VERSION 5.7 ;
BUSBITCHARS "[]" ;
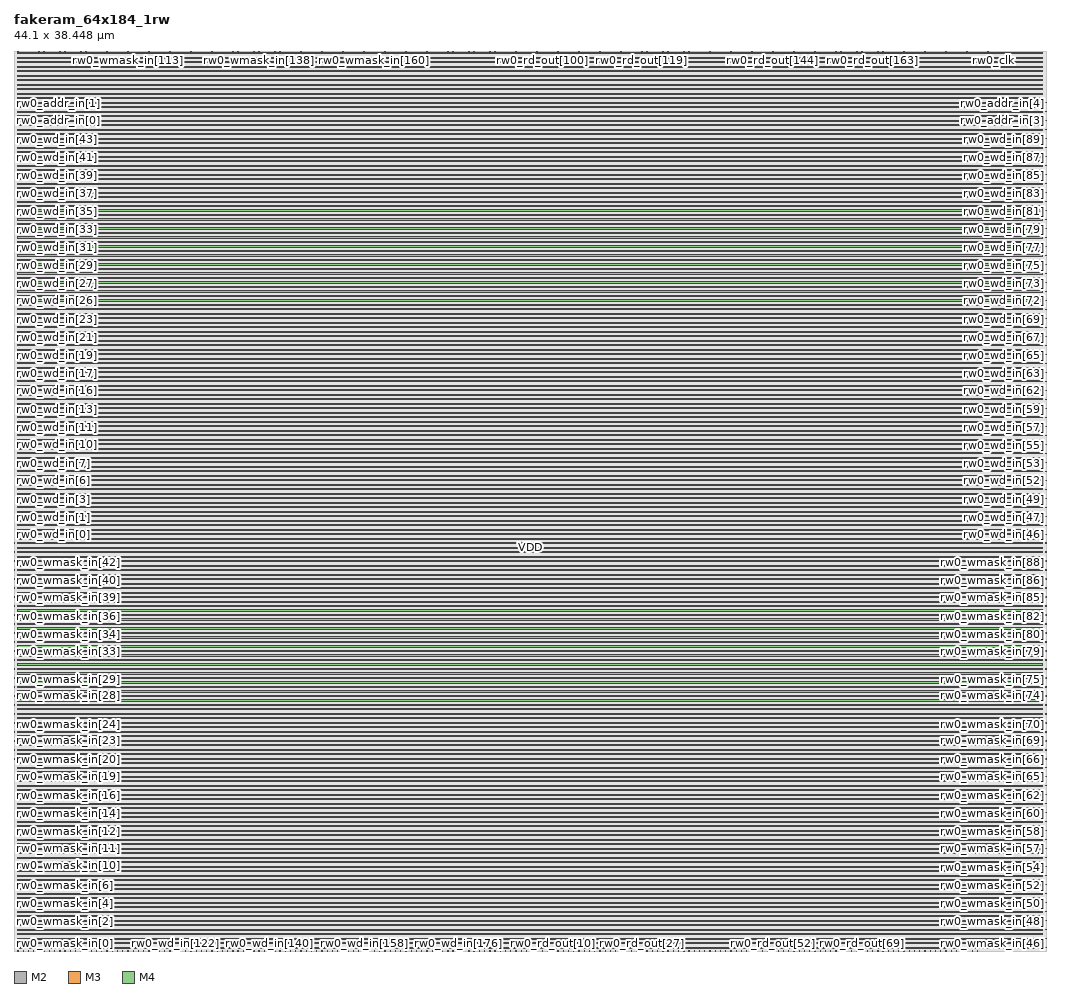
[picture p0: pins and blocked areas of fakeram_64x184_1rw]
MACRO fakeram_64x184_1rw
  FOREIGN fakeram_64x184_1rw 0 0 ;
  SYMMETRY X Y R90 ;
  SIZE 44.100 BY 38.448 ;
  CLASS BLOCK ;
  PIN rw0_wmask_in[0]
    DIRECTION INPUT ;
    USE SIGNAL ;
    SHAPE ABUTMENT ;
    PORT
      LAYER M2 ;
      RECT 0.000 0.138 0.036 0.150 ;
    END
  END rw0_wmask_in[0]
  PIN rw0_wmask_in[1]
    DIRECTION INPUT ;
    USE SIGNAL ;
    SHAPE ABUTMENT ;
    PORT
      LAYER M2 ;
      RECT 0.000 0.522 0.036 0.534 ;
    END
  END rw0_wmask_in[1]
  PIN rw0_wmask_in[2]
    DIRECTION INPUT ;
    USE SIGNAL ;
    SHAPE ABUTMENT ;
    PORT
      LAYER M2 ;
      RECT 0.000 0.906 0.036 0.918 ;
    END
  END rw0_wmask_in[2]
  PIN rw0_wmask_in[3]
    DIRECTION INPUT ;
    USE SIGNAL ;
    SHAPE ABUTMENT ;
    PORT
      LAYER M2 ;
      RECT 0.000 1.290 0.036 1.302 ;
    END
  END rw0_wmask_in[3]
  PIN rw0_wmask_in[4]
    DIRECTION INPUT ;
    USE SIGNAL ;
    SHAPE ABUTMENT ;
    PORT
      LAYER M2 ;
      RECT 0.000 1.674 0.036 1.686 ;
    END
  END rw0_wmask_in[4]
  PIN rw0_wmask_in[5]
    DIRECTION INPUT ;
    USE SIGNAL ;
    SHAPE ABUTMENT ;
    PORT
      LAYER M2 ;
      RECT 0.000 2.058 0.036 2.070 ;
    END
  END rw0_wmask_in[5]
  PIN rw0_wmask_in[6]
    DIRECTION INPUT ;
    USE SIGNAL ;
    SHAPE ABUTMENT ;
    PORT
      LAYER M2 ;
      RECT 0.000 2.442 0.036 2.454 ;
    END
  END rw0_wmask_in[6]
  PIN rw0_wmask_in[7]
    DIRECTION INPUT ;
    USE SIGNAL ;
    SHAPE ABUTMENT ;
    PORT
      LAYER M2 ;
      RECT 0.000 2.826 0.036 2.838 ;
    END
  END rw0_wmask_in[7]
  PIN rw0_wmask_in[8]
    DIRECTION INPUT ;
    USE SIGNAL ;
    SHAPE ABUTMENT ;
    PORT
      LAYER M2 ;
      RECT 0.000 3.210 0.036 3.222 ;
    END
  END rw0_wmask_in[8]
  PIN rw0_wmask_in[9]
    DIRECTION INPUT ;
    USE SIGNAL ;
    SHAPE ABUTMENT ;
    PORT
      LAYER M2 ;
      RECT 0.000 3.594 0.036 3.606 ;
    END
  END rw0_wmask_in[9]
  PIN rw0_wmask_in[10]
    DIRECTION INPUT ;
    USE SIGNAL ;
    SHAPE ABUTMENT ;
    PORT
      LAYER M2 ;
      RECT 0.000 3.978 0.036 3.990 ;
    END
  END rw0_wmask_in[10]
  PIN rw0_wmask_in[11]
    DIRECTION INPUT ;
    USE SIGNAL ;
    SHAPE ABUTMENT ;
    PORT
      LAYER M2 ;
      RECT 0.000 4.362 0.036 4.374 ;
    END
  END rw0_wmask_in[11]
  PIN rw0_wmask_in[12]
    DIRECTION INPUT ;
    USE SIGNAL ;
    SHAPE ABUTMENT ;
    PORT
      LAYER M2 ;
      RECT 0.000 4.746 0.036 4.758 ;
    END
  END rw0_wmask_in[12]
  PIN rw0_wmask_in[13]
    DIRECTION INPUT ;
    USE SIGNAL ;
    SHAPE ABUTMENT ;
    PORT
      LAYER M2 ;
      RECT 0.000 5.130 0.036 5.142 ;
    END
  END rw0_wmask_in[13]
  PIN rw0_wmask_in[14]
    DIRECTION INPUT ;
    USE SIGNAL ;
    SHAPE ABUTMENT ;
    PORT
      LAYER M2 ;
      RECT 0.000 5.514 0.036 5.526 ;
    END
  END rw0_wmask_in[14]
  PIN rw0_wmask_in[15]
    DIRECTION INPUT ;
    USE SIGNAL ;
    SHAPE ABUTMENT ;
    PORT
      LAYER M2 ;
      RECT 0.000 5.898 0.036 5.910 ;
    END
  END rw0_wmask_in[15]
  PIN rw0_wmask_in[16]
    DIRECTION INPUT ;
    USE SIGNAL ;
    SHAPE ABUTMENT ;
    PORT
      LAYER M2 ;
      RECT 0.000 6.282 0.036 6.294 ;
    END
  END rw0_wmask_in[16]
  PIN rw0_wmask_in[17]
    DIRECTION INPUT ;
    USE SIGNAL ;
    SHAPE ABUTMENT ;
    PORT
      LAYER M2 ;
      RECT 0.000 6.666 0.036 6.678 ;
    END
  END rw0_wmask_in[17]
  PIN rw0_wmask_in[18]
    DIRECTION INPUT ;
    USE SIGNAL ;
    SHAPE ABUTMENT ;
    PORT
      LAYER M2 ;
      RECT 0.000 7.050 0.036 7.062 ;
    END
  END rw0_wmask_in[18]
  PIN rw0_wmask_in[19]
    DIRECTION INPUT ;
    USE SIGNAL ;
    SHAPE ABUTMENT ;
    PORT
      LAYER M2 ;
      RECT 0.000 7.434 0.036 7.446 ;
    END
  END rw0_wmask_in[19]
  PIN rw0_wmask_in[20]
    DIRECTION INPUT ;
    USE SIGNAL ;
    SHAPE ABUTMENT ;
    PORT
      LAYER M2 ;
      RECT 0.000 7.818 0.036 7.830 ;
    END
  END rw0_wmask_in[20]
  PIN rw0_wmask_in[21]
    DIRECTION INPUT ;
    USE SIGNAL ;
    SHAPE ABUTMENT ;
    PORT
      LAYER M2 ;
      RECT 0.000 8.202 0.036 8.214 ;
    END
  END rw0_wmask_in[21]
  PIN rw0_wmask_in[22]
    DIRECTION INPUT ;
    USE SIGNAL ;
    SHAPE ABUTMENT ;
    PORT
      LAYER M2 ;
      RECT 0.000 8.586 0.036 8.598 ;
    END
  END rw0_wmask_in[22]
  PIN rw0_wmask_in[23]
    DIRECTION INPUT ;
    USE SIGNAL ;
    SHAPE ABUTMENT ;
    PORT
      LAYER M2 ;
      RECT 0.000 8.970 0.036 8.982 ;
    END
  END rw0_wmask_in[23]
  PIN rw0_wmask_in[24]
    DIRECTION INPUT ;
    USE SIGNAL ;
    SHAPE ABUTMENT ;
    PORT
      LAYER M2 ;
      RECT 0.000 9.354 0.036 9.366 ;
    END
  END rw0_wmask_in[24]
  PIN rw0_wmask_in[25]
    DIRECTION INPUT ;
    USE SIGNAL ;
    SHAPE ABUTMENT ;
    PORT
      LAYER M2 ;
      RECT 0.000 9.738 0.036 9.750 ;
    END
  END rw0_wmask_in[25]
  PIN rw0_wmask_in[26]
    DIRECTION INPUT ;
    USE SIGNAL ;
    SHAPE ABUTMENT ;
    PORT
      LAYER M2 ;
      RECT 0.000 10.122 0.036 10.134 ;
    END
  END rw0_wmask_in[26]
  PIN rw0_wmask_in[27]
    DIRECTION INPUT ;
    USE SIGNAL ;
    SHAPE ABUTMENT ;
    PORT
      LAYER M2 ;
      RECT 0.000 10.506 0.036 10.518 ;
    END
  END rw0_wmask_in[27]
  PIN rw0_wmask_in[28]
    DIRECTION INPUT ;
    USE SIGNAL ;
    SHAPE ABUTMENT ;
    PORT
      LAYER M2 ;
      RECT 0.000 10.890 0.036 10.902 ;
    END
  END rw0_wmask_in[28]
  PIN rw0_wmask_in[29]
    DIRECTION INPUT ;
    USE SIGNAL ;
    SHAPE ABUTMENT ;
    PORT
      LAYER M2 ;
      RECT 0.000 11.274 0.036 11.286 ;
    END
  END rw0_wmask_in[29]
  PIN rw0_wmask_in[30]
    DIRECTION INPUT ;
    USE SIGNAL ;
    SHAPE ABUTMENT ;
    PORT
      LAYER M2 ;
      RECT 0.000 11.658 0.036 11.670 ;
    END
  END rw0_wmask_in[30]
  PIN rw0_wmask_in[31]
    DIRECTION INPUT ;
    USE SIGNAL ;
    SHAPE ABUTMENT ;
    PORT
      LAYER M2 ;
      RECT 0.000 12.042 0.036 12.054 ;
    END
  END rw0_wmask_in[31]
  PIN rw0_wmask_in[32]
    DIRECTION INPUT ;
    USE SIGNAL ;
    SHAPE ABUTMENT ;
    PORT
      LAYER M2 ;
      RECT 0.000 12.426 0.036 12.438 ;
    END
  END rw0_wmask_in[32]
  PIN rw0_wmask_in[33]
    DIRECTION INPUT ;
    USE SIGNAL ;
    SHAPE ABUTMENT ;
    PORT
      LAYER M2 ;
      RECT 0.000 12.810 0.036 12.822 ;
    END
  END rw0_wmask_in[33]
  PIN rw0_wmask_in[34]
    DIRECTION INPUT ;
    USE SIGNAL ;
    SHAPE ABUTMENT ;
    PORT
      LAYER M2 ;
      RECT 0.000 13.194 0.036 13.206 ;
    END
  END rw0_wmask_in[34]
  PIN rw0_wmask_in[35]
    DIRECTION INPUT ;
    USE SIGNAL ;
    SHAPE ABUTMENT ;
    PORT
      LAYER M2 ;
      RECT 0.000 13.578 0.036 13.590 ;
    END
  END rw0_wmask_in[35]
  PIN rw0_wmask_in[36]
    DIRECTION INPUT ;
    USE SIGNAL ;
    SHAPE ABUTMENT ;
    PORT
      LAYER M2 ;
      RECT 0.000 13.962 0.036 13.974 ;
    END
  END rw0_wmask_in[36]
  PIN rw0_wmask_in[37]
    DIRECTION INPUT ;
    USE SIGNAL ;
    SHAPE ABUTMENT ;
    PORT
      LAYER M2 ;
      RECT 0.000 14.346 0.036 14.358 ;
    END
  END rw0_wmask_in[37]
  PIN rw0_wmask_in[38]
    DIRECTION INPUT ;
    USE SIGNAL ;
    SHAPE ABUTMENT ;
    PORT
      LAYER M2 ;
      RECT 0.000 14.730 0.036 14.742 ;
    END
  END rw0_wmask_in[38]
  PIN rw0_wmask_in[39]
    DIRECTION INPUT ;
    USE SIGNAL ;
    SHAPE ABUTMENT ;
    PORT
      LAYER M2 ;
      RECT 0.000 15.114 0.036 15.126 ;
    END
  END rw0_wmask_in[39]
  PIN rw0_wmask_in[40]
    DIRECTION INPUT ;
    USE SIGNAL ;
    SHAPE ABUTMENT ;
    PORT
      LAYER M2 ;
      RECT 0.000 15.498 0.036 15.510 ;
    END
  END rw0_wmask_in[40]
  PIN rw0_wmask_in[41]
    DIRECTION INPUT ;
    USE SIGNAL ;
    SHAPE ABUTMENT ;
    PORT
      LAYER M2 ;
      RECT 0.000 15.882 0.036 15.894 ;
    END
  END rw0_wmask_in[41]
  PIN rw0_wmask_in[42]
    DIRECTION INPUT ;
    USE SIGNAL ;
    SHAPE ABUTMENT ;
    PORT
      LAYER M2 ;
      RECT 0.000 16.266 0.036 16.278 ;
    END
  END rw0_wmask_in[42]
  PIN rw0_wmask_in[43]
    DIRECTION INPUT ;
    USE SIGNAL ;
    SHAPE ABUTMENT ;
    PORT
      LAYER M2 ;
      RECT 0.000 16.650 0.036 16.662 ;
    END
  END rw0_wmask_in[43]
  PIN rw0_wmask_in[44]
    DIRECTION INPUT ;
    USE SIGNAL ;
    SHAPE ABUTMENT ;
    PORT
      LAYER M2 ;
      RECT 0.000 17.034 0.036 17.046 ;
    END
  END rw0_wmask_in[44]
  PIN rw0_wmask_in[45]
    DIRECTION INPUT ;
    USE SIGNAL ;
    SHAPE ABUTMENT ;
    PORT
      LAYER M2 ;
      RECT 0.000 17.418 0.036 17.430 ;
    END
  END rw0_wmask_in[45]
  PIN rw0_wmask_in[46]
    DIRECTION INPUT ;
    USE SIGNAL ;
    SHAPE ABUTMENT ;
    PORT
      LAYER M2 ;
      RECT 44.064 0.138 44.100 0.150 ;
    END
  END rw0_wmask_in[46]
  PIN rw0_wmask_in[47]
    DIRECTION INPUT ;
    USE SIGNAL ;
    SHAPE ABUTMENT ;
    PORT
      LAYER M2 ;
      RECT 44.064 0.522 44.100 0.534 ;
    END
  END rw0_wmask_in[47]
  PIN rw0_wmask_in[48]
    DIRECTION INPUT ;
    USE SIGNAL ;
    SHAPE ABUTMENT ;
    PORT
      LAYER M2 ;
      RECT 44.064 0.906 44.100 0.918 ;
    END
  END rw0_wmask_in[48]
  PIN rw0_wmask_in[49]
    DIRECTION INPUT ;
    USE SIGNAL ;
    SHAPE ABUTMENT ;
    PORT
      LAYER M2 ;
      RECT 44.064 1.290 44.100 1.302 ;
    END
  END rw0_wmask_in[49]
  PIN rw0_wmask_in[50]
    DIRECTION INPUT ;
    USE SIGNAL ;
    SHAPE ABUTMENT ;
    PORT
      LAYER M2 ;
      RECT 44.064 1.674 44.100 1.686 ;
    END
  END rw0_wmask_in[50]
  PIN rw0_wmask_in[51]
    DIRECTION INPUT ;
    USE SIGNAL ;
    SHAPE ABUTMENT ;
    PORT
      LAYER M2 ;
      RECT 44.064 2.058 44.100 2.070 ;
    END
  END rw0_wmask_in[51]
  PIN rw0_wmask_in[52]
    DIRECTION INPUT ;
    USE SIGNAL ;
    SHAPE ABUTMENT ;
    PORT
      LAYER M2 ;
      RECT 44.064 2.442 44.100 2.454 ;
    END
  END rw0_wmask_in[52]
  PIN rw0_wmask_in[53]
    DIRECTION INPUT ;
    USE SIGNAL ;
    SHAPE ABUTMENT ;
    PORT
      LAYER M2 ;
      RECT 44.064 2.826 44.100 2.838 ;
    END
  END rw0_wmask_in[53]
  PIN rw0_wmask_in[54]
    DIRECTION INPUT ;
    USE SIGNAL ;
    SHAPE ABUTMENT ;
    PORT
      LAYER M2 ;
      RECT 44.064 3.210 44.100 3.222 ;
    END
  END rw0_wmask_in[54]
  PIN rw0_wmask_in[55]
    DIRECTION INPUT ;
    USE SIGNAL ;
    SHAPE ABUTMENT ;
    PORT
      LAYER M2 ;
      RECT 44.064 3.594 44.100 3.606 ;
    END
  END rw0_wmask_in[55]
  PIN rw0_wmask_in[56]
    DIRECTION INPUT ;
    USE SIGNAL ;
    SHAPE ABUTMENT ;
    PORT
      LAYER M2 ;
      RECT 44.064 3.978 44.100 3.990 ;
    END
  END rw0_wmask_in[56]
  PIN rw0_wmask_in[57]
    DIRECTION INPUT ;
    USE SIGNAL ;
    SHAPE ABUTMENT ;
    PORT
      LAYER M2 ;
      RECT 44.064 4.362 44.100 4.374 ;
    END
  END rw0_wmask_in[57]
  PIN rw0_wmask_in[58]
    DIRECTION INPUT ;
    USE SIGNAL ;
    SHAPE ABUTMENT ;
    PORT
      LAYER M2 ;
      RECT 44.064 4.746 44.100 4.758 ;
    END
  END rw0_wmask_in[58]
  PIN rw0_wmask_in[59]
    DIRECTION INPUT ;
    USE SIGNAL ;
    SHAPE ABUTMENT ;
    PORT
      LAYER M2 ;
      RECT 44.064 5.130 44.100 5.142 ;
    END
  END rw0_wmask_in[59]
  PIN rw0_wmask_in[60]
    DIRECTION INPUT ;
    USE SIGNAL ;
    SHAPE ABUTMENT ;
    PORT
      LAYER M2 ;
      RECT 44.064 5.514 44.100 5.526 ;
    END
  END rw0_wmask_in[60]
  PIN rw0_wmask_in[61]
    DIRECTION INPUT ;
    USE SIGNAL ;
    SHAPE ABUTMENT ;
    PORT
      LAYER M2 ;
      RECT 44.064 5.898 44.100 5.910 ;
    END
  END rw0_wmask_in[61]
  PIN rw0_wmask_in[62]
    DIRECTION INPUT ;
    USE SIGNAL ;
    SHAPE ABUTMENT ;
    PORT
      LAYER M2 ;
      RECT 44.064 6.282 44.100 6.294 ;
    END
  END rw0_wmask_in[62]
  PIN rw0_wmask_in[63]
    DIRECTION INPUT ;
    USE SIGNAL ;
    SHAPE ABUTMENT ;
    PORT
      LAYER M2 ;
      RECT 44.064 6.666 44.100 6.678 ;
    END
  END rw0_wmask_in[63]
  PIN rw0_wmask_in[64]
    DIRECTION INPUT ;
    USE SIGNAL ;
    SHAPE ABUTMENT ;
    PORT
      LAYER M2 ;
      RECT 44.064 7.050 44.100 7.062 ;
    END
  END rw0_wmask_in[64]
  PIN rw0_wmask_in[65]
    DIRECTION INPUT ;
    USE SIGNAL ;
    SHAPE ABUTMENT ;
    PORT
      LAYER M2 ;
      RECT 44.064 7.434 44.100 7.446 ;
    END
  END rw0_wmask_in[65]
  PIN rw0_wmask_in[66]
    DIRECTION INPUT ;
    USE SIGNAL ;
    SHAPE ABUTMENT ;
    PORT
      LAYER M2 ;
      RECT 44.064 7.818 44.100 7.830 ;
    END
  END rw0_wmask_in[66]
  PIN rw0_wmask_in[67]
    DIRECTION INPUT ;
    USE SIGNAL ;
    SHAPE ABUTMENT ;
    PORT
      LAYER M2 ;
      RECT 44.064 8.202 44.100 8.214 ;
    END
  END rw0_wmask_in[67]
  PIN rw0_wmask_in[68]
    DIRECTION INPUT ;
    USE SIGNAL ;
    SHAPE ABUTMENT ;
    PORT
      LAYER M2 ;
      RECT 44.064 8.586 44.100 8.598 ;
    END
  END rw0_wmask_in[68]
  PIN rw0_wmask_in[69]
    DIRECTION INPUT ;
    USE SIGNAL ;
    SHAPE ABUTMENT ;
    PORT
      LAYER M2 ;
      RECT 44.064 8.970 44.100 8.982 ;
    END
  END rw0_wmask_in[69]
  PIN rw0_wmask_in[70]
    DIRECTION INPUT ;
    USE SIGNAL ;
    SHAPE ABUTMENT ;
    PORT
      LAYER M2 ;
      RECT 44.064 9.354 44.100 9.366 ;
    END
  END rw0_wmask_in[70]
  PIN rw0_wmask_in[71]
    DIRECTION INPUT ;
    USE SIGNAL ;
    SHAPE ABUTMENT ;
    PORT
      LAYER M2 ;
      RECT 44.064 9.738 44.100 9.750 ;
    END
  END rw0_wmask_in[71]
  PIN rw0_wmask_in[72]
    DIRECTION INPUT ;
    USE SIGNAL ;
    SHAPE ABUTMENT ;
    PORT
      LAYER M2 ;
      RECT 44.064 10.122 44.100 10.134 ;
    END
  END rw0_wmask_in[72]
  PIN rw0_wmask_in[73]
    DIRECTION INPUT ;
    USE SIGNAL ;
    SHAPE ABUTMENT ;
    PORT
      LAYER M2 ;
      RECT 44.064 10.506 44.100 10.518 ;
    END
  END rw0_wmask_in[73]
  PIN rw0_wmask_in[74]
    DIRECTION INPUT ;
    USE SIGNAL ;
    SHAPE ABUTMENT ;
    PORT
      LAYER M2 ;
      RECT 44.064 10.890 44.100 10.902 ;
    END
  END rw0_wmask_in[74]
  PIN rw0_wmask_in[75]
    DIRECTION INPUT ;
    USE SIGNAL ;
    SHAPE ABUTMENT ;
    PORT
      LAYER M2 ;
      RECT 44.064 11.274 44.100 11.286 ;
    END
  END rw0_wmask_in[75]
  PIN rw0_wmask_in[76]
    DIRECTION INPUT ;
    USE SIGNAL ;
    SHAPE ABUTMENT ;
    PORT
      LAYER M2 ;
      RECT 44.064 11.658 44.100 11.670 ;
    END
  END rw0_wmask_in[76]
  PIN rw0_wmask_in[77]
    DIRECTION INPUT ;
    USE SIGNAL ;
    SHAPE ABUTMENT ;
    PORT
      LAYER M2 ;
      RECT 44.064 12.042 44.100 12.054 ;
    END
  END rw0_wmask_in[77]
  PIN rw0_wmask_in[78]
    DIRECTION INPUT ;
    USE SIGNAL ;
    SHAPE ABUTMENT ;
    PORT
      LAYER M2 ;
      RECT 44.064 12.426 44.100 12.438 ;
    END
  END rw0_wmask_in[78]
  PIN rw0_wmask_in[79]
    DIRECTION INPUT ;
    USE SIGNAL ;
    SHAPE ABUTMENT ;
    PORT
      LAYER M2 ;
      RECT 44.064 12.810 44.100 12.822 ;
    END
  END rw0_wmask_in[79]
  PIN rw0_wmask_in[80]
    DIRECTION INPUT ;
    USE SIGNAL ;
    SHAPE ABUTMENT ;
    PORT
      LAYER M2 ;
      RECT 44.064 13.194 44.100 13.206 ;
    END
  END rw0_wmask_in[80]
  PIN rw0_wmask_in[81]
    DIRECTION INPUT ;
    USE SIGNAL ;
    SHAPE ABUTMENT ;
    PORT
      LAYER M2 ;
      RECT 44.064 13.578 44.100 13.590 ;
    END
  END rw0_wmask_in[81]
  PIN rw0_wmask_in[82]
    DIRECTION INPUT ;
    USE SIGNAL ;
    SHAPE ABUTMENT ;
    PORT
      LAYER M2 ;
      RECT 44.064 13.962 44.100 13.974 ;
    END
  END rw0_wmask_in[82]
  PIN rw0_wmask_in[83]
    DIRECTION INPUT ;
    USE SIGNAL ;
    SHAPE ABUTMENT ;
    PORT
      LAYER M2 ;
      RECT 44.064 14.346 44.100 14.358 ;
    END
  END rw0_wmask_in[83]
  PIN rw0_wmask_in[84]
    DIRECTION INPUT ;
    USE SIGNAL ;
    SHAPE ABUTMENT ;
    PORT
      LAYER M2 ;
      RECT 44.064 14.730 44.100 14.742 ;
    END
  END rw0_wmask_in[84]
  PIN rw0_wmask_in[85]
    DIRECTION INPUT ;
    USE SIGNAL ;
    SHAPE ABUTMENT ;
    PORT
      LAYER M2 ;
      RECT 44.064 15.114 44.100 15.126 ;
    END
  END rw0_wmask_in[85]
  PIN rw0_wmask_in[86]
    DIRECTION INPUT ;
    USE SIGNAL ;
    SHAPE ABUTMENT ;
    PORT
      LAYER M2 ;
      RECT 44.064 15.498 44.100 15.510 ;
    END
  END rw0_wmask_in[86]
  PIN rw0_wmask_in[87]
    DIRECTION INPUT ;
    USE SIGNAL ;
    SHAPE ABUTMENT ;
    PORT
      LAYER M2 ;
      RECT 44.064 15.882 44.100 15.894 ;
    END
  END rw0_wmask_in[87]
  PIN rw0_wmask_in[88]
    DIRECTION INPUT ;
    USE SIGNAL ;
    SHAPE ABUTMENT ;
    PORT
      LAYER M2 ;
      RECT 44.064 16.266 44.100 16.278 ;
    END
  END rw0_wmask_in[88]
  PIN rw0_wmask_in[89]
    DIRECTION INPUT ;
    USE SIGNAL ;
    SHAPE ABUTMENT ;
    PORT
      LAYER M2 ;
      RECT 44.064 16.650 44.100 16.662 ;
    END
  END rw0_wmask_in[89]
  PIN rw0_wmask_in[90]
    DIRECTION INPUT ;
    USE SIGNAL ;
    SHAPE ABUTMENT ;
    PORT
      LAYER M2 ;
      RECT 44.064 17.034 44.100 17.046 ;
    END
  END rw0_wmask_in[90]
  PIN rw0_wmask_in[91]
    DIRECTION INPUT ;
    USE SIGNAL ;
    SHAPE ABUTMENT ;
    PORT
      LAYER M2 ;
      RECT 44.064 17.418 44.100 17.430 ;
    END
  END rw0_wmask_in[91]
  PIN rw0_wmask_in[92]
    DIRECTION INPUT ;
    USE SIGNAL ;
    SHAPE ABUTMENT ;
    PORT
      LAYER M3 ;
      RECT 0.161 38.406 0.175 38.448 ;
    END
  END rw0_wmask_in[92]
  PIN rw0_wmask_in[93]
    DIRECTION INPUT ;
    USE SIGNAL ;
    SHAPE ABUTMENT ;
    PORT
      LAYER M3 ;
      RECT 0.385 38.406 0.399 38.448 ;
    END
  END rw0_wmask_in[93]
  PIN rw0_wmask_in[94]
    DIRECTION INPUT ;
    USE SIGNAL ;
    SHAPE ABUTMENT ;
    PORT
      LAYER M3 ;
      RECT 0.609 38.406 0.623 38.448 ;
    END
  END rw0_wmask_in[94]
  PIN rw0_wmask_in[95]
    DIRECTION INPUT ;
    USE SIGNAL ;
    SHAPE ABUTMENT ;
    PORT
      LAYER M3 ;
      RECT 0.833 38.406 0.847 38.448 ;
    END
  END rw0_wmask_in[95]
  PIN rw0_wmask_in[96]
    DIRECTION INPUT ;
    USE SIGNAL ;
    SHAPE ABUTMENT ;
    PORT
      LAYER M3 ;
      RECT 1.057 38.406 1.071 38.448 ;
    END
  END rw0_wmask_in[96]
  PIN rw0_wmask_in[97]
    DIRECTION INPUT ;
    USE SIGNAL ;
    SHAPE ABUTMENT ;
    PORT
      LAYER M3 ;
      RECT 1.281 38.406 1.295 38.448 ;
    END
  END rw0_wmask_in[97]
  PIN rw0_wmask_in[98]
    DIRECTION INPUT ;
    USE SIGNAL ;
    SHAPE ABUTMENT ;
    PORT
      LAYER M3 ;
      RECT 1.505 38.406 1.519 38.448 ;
    END
  END rw0_wmask_in[98]
  PIN rw0_wmask_in[99]
    DIRECTION INPUT ;
    USE SIGNAL ;
    SHAPE ABUTMENT ;
    PORT
      LAYER M3 ;
      RECT 1.729 38.406 1.743 38.448 ;
    END
  END rw0_wmask_in[99]
  PIN rw0_wmask_in[100]
    DIRECTION INPUT ;
    USE SIGNAL ;
    SHAPE ABUTMENT ;
    PORT
      LAYER M3 ;
      RECT 1.953 38.406 1.967 38.448 ;
    END
  END rw0_wmask_in[100]
  PIN rw0_wmask_in[101]
    DIRECTION INPUT ;
    USE SIGNAL ;
    SHAPE ABUTMENT ;
    PORT
      LAYER M3 ;
      RECT 2.177 38.406 2.191 38.448 ;
    END
  END rw0_wmask_in[101]
  PIN rw0_wmask_in[102]
    DIRECTION INPUT ;
    USE SIGNAL ;
    SHAPE ABUTMENT ;
    PORT
      LAYER M3 ;
      RECT 2.401 38.406 2.415 38.448 ;
    END
  END rw0_wmask_in[102]
  PIN rw0_wmask_in[103]
    DIRECTION INPUT ;
    USE SIGNAL ;
    SHAPE ABUTMENT ;
    PORT
      LAYER M3 ;
      RECT 2.625 38.406 2.639 38.448 ;
    END
  END rw0_wmask_in[103]
  PIN rw0_wmask_in[104]
    DIRECTION INPUT ;
    USE SIGNAL ;
    SHAPE ABUTMENT ;
    PORT
      LAYER M3 ;
      RECT 2.849 38.406 2.863 38.448 ;
    END
  END rw0_wmask_in[104]
  PIN rw0_wmask_in[105]
    DIRECTION INPUT ;
    USE SIGNAL ;
    SHAPE ABUTMENT ;
    PORT
      LAYER M3 ;
      RECT 3.073 38.406 3.087 38.448 ;
    END
  END rw0_wmask_in[105]
  PIN rw0_wmask_in[106]
    DIRECTION INPUT ;
    USE SIGNAL ;
    SHAPE ABUTMENT ;
    PORT
      LAYER M3 ;
      RECT 3.297 38.406 3.311 38.448 ;
    END
  END rw0_wmask_in[106]
  PIN rw0_wmask_in[107]
    DIRECTION INPUT ;
    USE SIGNAL ;
    SHAPE ABUTMENT ;
    PORT
      LAYER M3 ;
      RECT 3.521 38.406 3.535 38.448 ;
    END
  END rw0_wmask_in[107]
  PIN rw0_wmask_in[108]
    DIRECTION INPUT ;
    USE SIGNAL ;
    SHAPE ABUTMENT ;
    PORT
      LAYER M3 ;
      RECT 3.745 38.406 3.759 38.448 ;
    END
  END rw0_wmask_in[108]
  PIN rw0_wmask_in[109]
    DIRECTION INPUT ;
    USE SIGNAL ;
    SHAPE ABUTMENT ;
    PORT
      LAYER M3 ;
      RECT 3.969 38.406 3.983 38.448 ;
    END
  END rw0_wmask_in[109]
  PIN rw0_wmask_in[110]
    DIRECTION INPUT ;
    USE SIGNAL ;
    SHAPE ABUTMENT ;
    PORT
      LAYER M3 ;
      RECT 4.193 38.406 4.207 38.448 ;
    END
  END rw0_wmask_in[110]
  PIN rw0_wmask_in[111]
    DIRECTION INPUT ;
    USE SIGNAL ;
    SHAPE ABUTMENT ;
    PORT
      LAYER M3 ;
      RECT 4.417 38.406 4.431 38.448 ;
    END
  END rw0_wmask_in[111]
  PIN rw0_wmask_in[112]
    DIRECTION INPUT ;
    USE SIGNAL ;
    SHAPE ABUTMENT ;
    PORT
      LAYER M3 ;
      RECT 4.641 38.406 4.655 38.448 ;
    END
  END rw0_wmask_in[112]
  PIN rw0_wmask_in[113]
    DIRECTION INPUT ;
    USE SIGNAL ;
    SHAPE ABUTMENT ;
    PORT
      LAYER M3 ;
      RECT 4.865 38.406 4.879 38.448 ;
    END
  END rw0_wmask_in[113]
  PIN rw0_wmask_in[114]
    DIRECTION INPUT ;
    USE SIGNAL ;
    SHAPE ABUTMENT ;
    PORT
      LAYER M3 ;
      RECT 5.089 38.406 5.103 38.448 ;
    END
  END rw0_wmask_in[114]
  PIN rw0_wmask_in[115]
    DIRECTION INPUT ;
    USE SIGNAL ;
    SHAPE ABUTMENT ;
    PORT
      LAYER M3 ;
      RECT 5.313 38.406 5.327 38.448 ;
    END
  END rw0_wmask_in[115]
  PIN rw0_wmask_in[116]
    DIRECTION INPUT ;
    USE SIGNAL ;
    SHAPE ABUTMENT ;
    PORT
      LAYER M3 ;
      RECT 5.537 38.406 5.551 38.448 ;
    END
  END rw0_wmask_in[116]
  PIN rw0_wmask_in[117]
    DIRECTION INPUT ;
    USE SIGNAL ;
    SHAPE ABUTMENT ;
    PORT
      LAYER M3 ;
      RECT 5.761 38.406 5.775 38.448 ;
    END
  END rw0_wmask_in[117]
  PIN rw0_wmask_in[118]
    DIRECTION INPUT ;
    USE SIGNAL ;
    SHAPE ABUTMENT ;
    PORT
      LAYER M3 ;
      RECT 5.985 38.406 5.999 38.448 ;
    END
  END rw0_wmask_in[118]
  PIN rw0_wmask_in[119]
    DIRECTION INPUT ;
    USE SIGNAL ;
    SHAPE ABUTMENT ;
    PORT
      LAYER M3 ;
      RECT 6.209 38.406 6.223 38.448 ;
    END
  END rw0_wmask_in[119]
  PIN rw0_wmask_in[120]
    DIRECTION INPUT ;
    USE SIGNAL ;
    SHAPE ABUTMENT ;
    PORT
      LAYER M3 ;
      RECT 6.433 38.406 6.447 38.448 ;
    END
  END rw0_wmask_in[120]
  PIN rw0_wmask_in[121]
    DIRECTION INPUT ;
    USE SIGNAL ;
    SHAPE ABUTMENT ;
    PORT
      LAYER M3 ;
      RECT 6.657 38.406 6.671 38.448 ;
    END
  END rw0_wmask_in[121]
  PIN rw0_wmask_in[122]
    DIRECTION INPUT ;
    USE SIGNAL ;
    SHAPE ABUTMENT ;
    PORT
      LAYER M3 ;
      RECT 6.881 38.406 6.895 38.448 ;
    END
  END rw0_wmask_in[122]
  PIN rw0_wmask_in[123]
    DIRECTION INPUT ;
    USE SIGNAL ;
    SHAPE ABUTMENT ;
    PORT
      LAYER M3 ;
      RECT 7.105 38.406 7.119 38.448 ;
    END
  END rw0_wmask_in[123]
  PIN rw0_wmask_in[124]
    DIRECTION INPUT ;
    USE SIGNAL ;
    SHAPE ABUTMENT ;
    PORT
      LAYER M3 ;
      RECT 7.329 38.406 7.343 38.448 ;
    END
  END rw0_wmask_in[124]
  PIN rw0_wmask_in[125]
    DIRECTION INPUT ;
    USE SIGNAL ;
    SHAPE ABUTMENT ;
    PORT
      LAYER M3 ;
      RECT 7.553 38.406 7.567 38.448 ;
    END
  END rw0_wmask_in[125]
  PIN rw0_wmask_in[126]
    DIRECTION INPUT ;
    USE SIGNAL ;
    SHAPE ABUTMENT ;
    PORT
      LAYER M3 ;
      RECT 7.777 38.406 7.791 38.448 ;
    END
  END rw0_wmask_in[126]
  PIN rw0_wmask_in[127]
    DIRECTION INPUT ;
    USE SIGNAL ;
    SHAPE ABUTMENT ;
    PORT
      LAYER M3 ;
      RECT 8.001 38.406 8.015 38.448 ;
    END
  END rw0_wmask_in[127]
  PIN rw0_wmask_in[128]
    DIRECTION INPUT ;
    USE SIGNAL ;
    SHAPE ABUTMENT ;
    PORT
      LAYER M3 ;
      RECT 8.225 38.406 8.239 38.448 ;
    END
  END rw0_wmask_in[128]
  PIN rw0_wmask_in[129]
    DIRECTION INPUT ;
    USE SIGNAL ;
    SHAPE ABUTMENT ;
    PORT
      LAYER M3 ;
      RECT 8.449 38.406 8.463 38.448 ;
    END
  END rw0_wmask_in[129]
  PIN rw0_wmask_in[130]
    DIRECTION INPUT ;
    USE SIGNAL ;
    SHAPE ABUTMENT ;
    PORT
      LAYER M3 ;
      RECT 8.673 38.406 8.687 38.448 ;
    END
  END rw0_wmask_in[130]
  PIN rw0_wmask_in[131]
    DIRECTION INPUT ;
    USE SIGNAL ;
    SHAPE ABUTMENT ;
    PORT
      LAYER M3 ;
      RECT 8.897 38.406 8.911 38.448 ;
    END
  END rw0_wmask_in[131]
  PIN rw0_wmask_in[132]
    DIRECTION INPUT ;
    USE SIGNAL ;
    SHAPE ABUTMENT ;
    PORT
      LAYER M3 ;
      RECT 9.121 38.406 9.135 38.448 ;
    END
  END rw0_wmask_in[132]
  PIN rw0_wmask_in[133]
    DIRECTION INPUT ;
    USE SIGNAL ;
    SHAPE ABUTMENT ;
    PORT
      LAYER M3 ;
      RECT 9.345 38.406 9.359 38.448 ;
    END
  END rw0_wmask_in[133]
  PIN rw0_wmask_in[134]
    DIRECTION INPUT ;
    USE SIGNAL ;
    SHAPE ABUTMENT ;
    PORT
      LAYER M3 ;
      RECT 9.569 38.406 9.583 38.448 ;
    END
  END rw0_wmask_in[134]
  PIN rw0_wmask_in[135]
    DIRECTION INPUT ;
    USE SIGNAL ;
    SHAPE ABUTMENT ;
    PORT
      LAYER M3 ;
      RECT 9.793 38.406 9.807 38.448 ;
    END
  END rw0_wmask_in[135]
  PIN rw0_wmask_in[136]
    DIRECTION INPUT ;
    USE SIGNAL ;
    SHAPE ABUTMENT ;
    PORT
      LAYER M3 ;
      RECT 10.017 38.406 10.031 38.448 ;
    END
  END rw0_wmask_in[136]
  PIN rw0_wmask_in[137]
    DIRECTION INPUT ;
    USE SIGNAL ;
    SHAPE ABUTMENT ;
    PORT
      LAYER M3 ;
      RECT 10.241 38.406 10.255 38.448 ;
    END
  END rw0_wmask_in[137]
  PIN rw0_wmask_in[138]
    DIRECTION INPUT ;
    USE SIGNAL ;
    SHAPE ABUTMENT ;
    PORT
      LAYER M3 ;
      RECT 10.465 38.406 10.479 38.448 ;
    END
  END rw0_wmask_in[138]
  PIN rw0_wmask_in[139]
    DIRECTION INPUT ;
    USE SIGNAL ;
    SHAPE ABUTMENT ;
    PORT
      LAYER M3 ;
      RECT 10.689 38.406 10.703 38.448 ;
    END
  END rw0_wmask_in[139]
  PIN rw0_wmask_in[140]
    DIRECTION INPUT ;
    USE SIGNAL ;
    SHAPE ABUTMENT ;
    PORT
      LAYER M3 ;
      RECT 10.913 38.406 10.927 38.448 ;
    END
  END rw0_wmask_in[140]
  PIN rw0_wmask_in[141]
    DIRECTION INPUT ;
    USE SIGNAL ;
    SHAPE ABUTMENT ;
    PORT
      LAYER M3 ;
      RECT 11.137 38.406 11.151 38.448 ;
    END
  END rw0_wmask_in[141]
  PIN rw0_wmask_in[142]
    DIRECTION INPUT ;
    USE SIGNAL ;
    SHAPE ABUTMENT ;
    PORT
      LAYER M3 ;
      RECT 11.361 38.406 11.375 38.448 ;
    END
  END rw0_wmask_in[142]
  PIN rw0_wmask_in[143]
    DIRECTION INPUT ;
    USE SIGNAL ;
    SHAPE ABUTMENT ;
    PORT
      LAYER M3 ;
      RECT 11.585 38.406 11.599 38.448 ;
    END
  END rw0_wmask_in[143]
  PIN rw0_wmask_in[144]
    DIRECTION INPUT ;
    USE SIGNAL ;
    SHAPE ABUTMENT ;
    PORT
      LAYER M3 ;
      RECT 11.809 38.406 11.823 38.448 ;
    END
  END rw0_wmask_in[144]
  PIN rw0_wmask_in[145]
    DIRECTION INPUT ;
    USE SIGNAL ;
    SHAPE ABUTMENT ;
    PORT
      LAYER M3 ;
      RECT 12.033 38.406 12.047 38.448 ;
    END
  END rw0_wmask_in[145]
  PIN rw0_wmask_in[146]
    DIRECTION INPUT ;
    USE SIGNAL ;
    SHAPE ABUTMENT ;
    PORT
      LAYER M3 ;
      RECT 12.257 38.406 12.271 38.448 ;
    END
  END rw0_wmask_in[146]
  PIN rw0_wmask_in[147]
    DIRECTION INPUT ;
    USE SIGNAL ;
    SHAPE ABUTMENT ;
    PORT
      LAYER M3 ;
      RECT 12.481 38.406 12.495 38.448 ;
    END
  END rw0_wmask_in[147]
  PIN rw0_wmask_in[148]
    DIRECTION INPUT ;
    USE SIGNAL ;
    SHAPE ABUTMENT ;
    PORT
      LAYER M3 ;
      RECT 12.705 38.406 12.719 38.448 ;
    END
  END rw0_wmask_in[148]
  PIN rw0_wmask_in[149]
    DIRECTION INPUT ;
    USE SIGNAL ;
    SHAPE ABUTMENT ;
    PORT
      LAYER M3 ;
      RECT 12.929 38.406 12.943 38.448 ;
    END
  END rw0_wmask_in[149]
  PIN rw0_wmask_in[150]
    DIRECTION INPUT ;
    USE SIGNAL ;
    SHAPE ABUTMENT ;
    PORT
      LAYER M3 ;
      RECT 13.153 38.406 13.167 38.448 ;
    END
  END rw0_wmask_in[150]
  PIN rw0_wmask_in[151]
    DIRECTION INPUT ;
    USE SIGNAL ;
    SHAPE ABUTMENT ;
    PORT
      LAYER M3 ;
      RECT 13.377 38.406 13.391 38.448 ;
    END
  END rw0_wmask_in[151]
  PIN rw0_wmask_in[152]
    DIRECTION INPUT ;
    USE SIGNAL ;
    SHAPE ABUTMENT ;
    PORT
      LAYER M3 ;
      RECT 13.601 38.406 13.615 38.448 ;
    END
  END rw0_wmask_in[152]
  PIN rw0_wmask_in[153]
    DIRECTION INPUT ;
    USE SIGNAL ;
    SHAPE ABUTMENT ;
    PORT
      LAYER M3 ;
      RECT 13.825 38.406 13.839 38.448 ;
    END
  END rw0_wmask_in[153]
  PIN rw0_wmask_in[154]
    DIRECTION INPUT ;
    USE SIGNAL ;
    SHAPE ABUTMENT ;
    PORT
      LAYER M3 ;
      RECT 14.049 38.406 14.063 38.448 ;
    END
  END rw0_wmask_in[154]
  PIN rw0_wmask_in[155]
    DIRECTION INPUT ;
    USE SIGNAL ;
    SHAPE ABUTMENT ;
    PORT
      LAYER M3 ;
      RECT 14.273 38.406 14.287 38.448 ;
    END
  END rw0_wmask_in[155]
  PIN rw0_wmask_in[156]
    DIRECTION INPUT ;
    USE SIGNAL ;
    SHAPE ABUTMENT ;
    PORT
      LAYER M3 ;
      RECT 14.497 38.406 14.511 38.448 ;
    END
  END rw0_wmask_in[156]
  PIN rw0_wmask_in[157]
    DIRECTION INPUT ;
    USE SIGNAL ;
    SHAPE ABUTMENT ;
    PORT
      LAYER M3 ;
      RECT 14.721 38.406 14.735 38.448 ;
    END
  END rw0_wmask_in[157]
  PIN rw0_wmask_in[158]
    DIRECTION INPUT ;
    USE SIGNAL ;
    SHAPE ABUTMENT ;
    PORT
      LAYER M3 ;
      RECT 14.945 38.406 14.959 38.448 ;
    END
  END rw0_wmask_in[158]
  PIN rw0_wmask_in[159]
    DIRECTION INPUT ;
    USE SIGNAL ;
    SHAPE ABUTMENT ;
    PORT
      LAYER M3 ;
      RECT 15.169 38.406 15.183 38.448 ;
    END
  END rw0_wmask_in[159]
  PIN rw0_wmask_in[160]
    DIRECTION INPUT ;
    USE SIGNAL ;
    SHAPE ABUTMENT ;
    PORT
      LAYER M3 ;
      RECT 15.393 38.406 15.407 38.448 ;
    END
  END rw0_wmask_in[160]
  PIN rw0_wmask_in[161]
    DIRECTION INPUT ;
    USE SIGNAL ;
    SHAPE ABUTMENT ;
    PORT
      LAYER M3 ;
      RECT 15.617 38.406 15.631 38.448 ;
    END
  END rw0_wmask_in[161]
  PIN rw0_wmask_in[162]
    DIRECTION INPUT ;
    USE SIGNAL ;
    SHAPE ABUTMENT ;
    PORT
      LAYER M3 ;
      RECT 15.841 38.406 15.855 38.448 ;
    END
  END rw0_wmask_in[162]
  PIN rw0_wmask_in[163]
    DIRECTION INPUT ;
    USE SIGNAL ;
    SHAPE ABUTMENT ;
    PORT
      LAYER M3 ;
      RECT 16.065 38.406 16.079 38.448 ;
    END
  END rw0_wmask_in[163]
  PIN rw0_wmask_in[164]
    DIRECTION INPUT ;
    USE SIGNAL ;
    SHAPE ABUTMENT ;
    PORT
      LAYER M3 ;
      RECT 16.289 38.406 16.303 38.448 ;
    END
  END rw0_wmask_in[164]
  PIN rw0_wmask_in[165]
    DIRECTION INPUT ;
    USE SIGNAL ;
    SHAPE ABUTMENT ;
    PORT
      LAYER M3 ;
      RECT 16.513 38.406 16.527 38.448 ;
    END
  END rw0_wmask_in[165]
  PIN rw0_wmask_in[166]
    DIRECTION INPUT ;
    USE SIGNAL ;
    SHAPE ABUTMENT ;
    PORT
      LAYER M3 ;
      RECT 16.737 38.406 16.751 38.448 ;
    END
  END rw0_wmask_in[166]
  PIN rw0_wmask_in[167]
    DIRECTION INPUT ;
    USE SIGNAL ;
    SHAPE ABUTMENT ;
    PORT
      LAYER M3 ;
      RECT 16.961 38.406 16.975 38.448 ;
    END
  END rw0_wmask_in[167]
  PIN rw0_wmask_in[168]
    DIRECTION INPUT ;
    USE SIGNAL ;
    SHAPE ABUTMENT ;
    PORT
      LAYER M3 ;
      RECT 17.185 38.406 17.199 38.448 ;
    END
  END rw0_wmask_in[168]
  PIN rw0_wmask_in[169]
    DIRECTION INPUT ;
    USE SIGNAL ;
    SHAPE ABUTMENT ;
    PORT
      LAYER M3 ;
      RECT 17.409 38.406 17.423 38.448 ;
    END
  END rw0_wmask_in[169]
  PIN rw0_wmask_in[170]
    DIRECTION INPUT ;
    USE SIGNAL ;
    SHAPE ABUTMENT ;
    PORT
      LAYER M3 ;
      RECT 17.633 38.406 17.647 38.448 ;
    END
  END rw0_wmask_in[170]
  PIN rw0_wmask_in[171]
    DIRECTION INPUT ;
    USE SIGNAL ;
    SHAPE ABUTMENT ;
    PORT
      LAYER M3 ;
      RECT 17.857 38.406 17.871 38.448 ;
    END
  END rw0_wmask_in[171]
  PIN rw0_wmask_in[172]
    DIRECTION INPUT ;
    USE SIGNAL ;
    SHAPE ABUTMENT ;
    PORT
      LAYER M3 ;
      RECT 18.081 38.406 18.095 38.448 ;
    END
  END rw0_wmask_in[172]
  PIN rw0_wmask_in[173]
    DIRECTION INPUT ;
    USE SIGNAL ;
    SHAPE ABUTMENT ;
    PORT
      LAYER M3 ;
      RECT 18.305 38.406 18.319 38.448 ;
    END
  END rw0_wmask_in[173]
  PIN rw0_wmask_in[174]
    DIRECTION INPUT ;
    USE SIGNAL ;
    SHAPE ABUTMENT ;
    PORT
      LAYER M3 ;
      RECT 18.529 38.406 18.543 38.448 ;
    END
  END rw0_wmask_in[174]
  PIN rw0_wmask_in[175]
    DIRECTION INPUT ;
    USE SIGNAL ;
    SHAPE ABUTMENT ;
    PORT
      LAYER M3 ;
      RECT 18.753 38.406 18.767 38.448 ;
    END
  END rw0_wmask_in[175]
  PIN rw0_wmask_in[176]
    DIRECTION INPUT ;
    USE SIGNAL ;
    SHAPE ABUTMENT ;
    PORT
      LAYER M3 ;
      RECT 18.977 38.406 18.991 38.448 ;
    END
  END rw0_wmask_in[176]
  PIN rw0_wmask_in[177]
    DIRECTION INPUT ;
    USE SIGNAL ;
    SHAPE ABUTMENT ;
    PORT
      LAYER M3 ;
      RECT 19.201 38.406 19.215 38.448 ;
    END
  END rw0_wmask_in[177]
  PIN rw0_wmask_in[178]
    DIRECTION INPUT ;
    USE SIGNAL ;
    SHAPE ABUTMENT ;
    PORT
      LAYER M3 ;
      RECT 19.425 38.406 19.439 38.448 ;
    END
  END rw0_wmask_in[178]
  PIN rw0_wmask_in[179]
    DIRECTION INPUT ;
    USE SIGNAL ;
    SHAPE ABUTMENT ;
    PORT
      LAYER M3 ;
      RECT 19.649 38.406 19.663 38.448 ;
    END
  END rw0_wmask_in[179]
  PIN rw0_wmask_in[180]
    DIRECTION INPUT ;
    USE SIGNAL ;
    SHAPE ABUTMENT ;
    PORT
      LAYER M3 ;
      RECT 19.873 38.406 19.887 38.448 ;
    END
  END rw0_wmask_in[180]
  PIN rw0_wmask_in[181]
    DIRECTION INPUT ;
    USE SIGNAL ;
    SHAPE ABUTMENT ;
    PORT
      LAYER M3 ;
      RECT 20.097 38.406 20.111 38.448 ;
    END
  END rw0_wmask_in[181]
  PIN rw0_wmask_in[182]
    DIRECTION INPUT ;
    USE SIGNAL ;
    SHAPE ABUTMENT ;
    PORT
      LAYER M3 ;
      RECT 20.321 38.406 20.335 38.448 ;
    END
  END rw0_wmask_in[182]
  PIN rw0_wmask_in[183]
    DIRECTION INPUT ;
    USE SIGNAL ;
    SHAPE ABUTMENT ;
    PORT
      LAYER M3 ;
      RECT 20.545 38.406 20.559 38.448 ;
    END
  END rw0_wmask_in[183]
  PIN rw0_wd_in[0]
    DIRECTION INPUT ;
    USE SIGNAL ;
    SHAPE ABUTMENT ;
    PORT
      LAYER M2 ;
      RECT 0.000 17.802 0.036 17.814 ;
    END
  END rw0_wd_in[0]
  PIN rw0_wd_in[1]
    DIRECTION INPUT ;
    USE SIGNAL ;
    SHAPE ABUTMENT ;
    PORT
      LAYER M2 ;
      RECT 0.000 18.186 0.036 18.198 ;
    END
  END rw0_wd_in[1]
  PIN rw0_wd_in[2]
    DIRECTION INPUT ;
    USE SIGNAL ;
    SHAPE ABUTMENT ;
    PORT
      LAYER M2 ;
      RECT 0.000 18.570 0.036 18.582 ;
    END
  END rw0_wd_in[2]
  PIN rw0_wd_in[3]
    DIRECTION INPUT ;
    USE SIGNAL ;
    SHAPE ABUTMENT ;
    PORT
      LAYER M2 ;
      RECT 0.000 18.954 0.036 18.966 ;
    END
  END rw0_wd_in[3]
  PIN rw0_wd_in[4]
    DIRECTION INPUT ;
    USE SIGNAL ;
    SHAPE ABUTMENT ;
    PORT
      LAYER M2 ;
      RECT 0.000 19.338 0.036 19.350 ;
    END
  END rw0_wd_in[4]
  PIN rw0_wd_in[5]
    DIRECTION INPUT ;
    USE SIGNAL ;
    SHAPE ABUTMENT ;
    PORT
      LAYER M2 ;
      RECT 0.000 19.722 0.036 19.734 ;
    END
  END rw0_wd_in[5]
  PIN rw0_wd_in[6]
    DIRECTION INPUT ;
    USE SIGNAL ;
    SHAPE ABUTMENT ;
    PORT
      LAYER M2 ;
      RECT 0.000 20.106 0.036 20.118 ;
    END
  END rw0_wd_in[6]
  PIN rw0_wd_in[7]
    DIRECTION INPUT ;
    USE SIGNAL ;
    SHAPE ABUTMENT ;
    PORT
      LAYER M2 ;
      RECT 0.000 20.490 0.036 20.502 ;
    END
  END rw0_wd_in[7]
  PIN rw0_wd_in[8]
    DIRECTION INPUT ;
    USE SIGNAL ;
    SHAPE ABUTMENT ;
    PORT
      LAYER M2 ;
      RECT 0.000 20.874 0.036 20.886 ;
    END
  END rw0_wd_in[8]
  PIN rw0_wd_in[9]
    DIRECTION INPUT ;
    USE SIGNAL ;
    SHAPE ABUTMENT ;
    PORT
      LAYER M2 ;
      RECT 0.000 21.258 0.036 21.270 ;
    END
  END rw0_wd_in[9]
  PIN rw0_wd_in[10]
    DIRECTION INPUT ;
    USE SIGNAL ;
    SHAPE ABUTMENT ;
    PORT
      LAYER M2 ;
      RECT 0.000 21.642 0.036 21.654 ;
    END
  END rw0_wd_in[10]
  PIN rw0_wd_in[11]
    DIRECTION INPUT ;
    USE SIGNAL ;
    SHAPE ABUTMENT ;
    PORT
      LAYER M2 ;
      RECT 0.000 22.026 0.036 22.038 ;
    END
  END rw0_wd_in[11]
  PIN rw0_wd_in[12]
    DIRECTION INPUT ;
    USE SIGNAL ;
    SHAPE ABUTMENT ;
    PORT
      LAYER M2 ;
      RECT 0.000 22.410 0.036 22.422 ;
    END
  END rw0_wd_in[12]
  PIN rw0_wd_in[13]
    DIRECTION INPUT ;
    USE SIGNAL ;
    SHAPE ABUTMENT ;
    PORT
      LAYER M2 ;
      RECT 0.000 22.794 0.036 22.806 ;
    END
  END rw0_wd_in[13]
  PIN rw0_wd_in[14]
    DIRECTION INPUT ;
    USE SIGNAL ;
    SHAPE ABUTMENT ;
    PORT
      LAYER M2 ;
      RECT 0.000 23.178 0.036 23.190 ;
    END
  END rw0_wd_in[14]
  PIN rw0_wd_in[15]
    DIRECTION INPUT ;
    USE SIGNAL ;
    SHAPE ABUTMENT ;
    PORT
      LAYER M2 ;
      RECT 0.000 23.562 0.036 23.574 ;
    END
  END rw0_wd_in[15]
  PIN rw0_wd_in[16]
    DIRECTION INPUT ;
    USE SIGNAL ;
    SHAPE ABUTMENT ;
    PORT
      LAYER M2 ;
      RECT 0.000 23.946 0.036 23.958 ;
    END
  END rw0_wd_in[16]
  PIN rw0_wd_in[17]
    DIRECTION INPUT ;
    USE SIGNAL ;
    SHAPE ABUTMENT ;
    PORT
      LAYER M2 ;
      RECT 0.000 24.330 0.036 24.342 ;
    END
  END rw0_wd_in[17]
  PIN rw0_wd_in[18]
    DIRECTION INPUT ;
    USE SIGNAL ;
    SHAPE ABUTMENT ;
    PORT
      LAYER M2 ;
      RECT 0.000 24.714 0.036 24.726 ;
    END
  END rw0_wd_in[18]
  PIN rw0_wd_in[19]
    DIRECTION INPUT ;
    USE SIGNAL ;
    SHAPE ABUTMENT ;
    PORT
      LAYER M2 ;
      RECT 0.000 25.098 0.036 25.110 ;
    END
  END rw0_wd_in[19]
  PIN rw0_wd_in[20]
    DIRECTION INPUT ;
    USE SIGNAL ;
    SHAPE ABUTMENT ;
    PORT
      LAYER M2 ;
      RECT 0.000 25.482 0.036 25.494 ;
    END
  END rw0_wd_in[20]
  PIN rw0_wd_in[21]
    DIRECTION INPUT ;
    USE SIGNAL ;
    SHAPE ABUTMENT ;
    PORT
      LAYER M2 ;
      RECT 0.000 25.866 0.036 25.878 ;
    END
  END rw0_wd_in[21]
  PIN rw0_wd_in[22]
    DIRECTION INPUT ;
    USE SIGNAL ;
    SHAPE ABUTMENT ;
    PORT
      LAYER M2 ;
      RECT 0.000 26.250 0.036 26.262 ;
    END
  END rw0_wd_in[22]
  PIN rw0_wd_in[23]
    DIRECTION INPUT ;
    USE SIGNAL ;
    SHAPE ABUTMENT ;
    PORT
      LAYER M2 ;
      RECT 0.000 26.634 0.036 26.646 ;
    END
  END rw0_wd_in[23]
  PIN rw0_wd_in[24]
    DIRECTION INPUT ;
    USE SIGNAL ;
    SHAPE ABUTMENT ;
    PORT
      LAYER M2 ;
      RECT 0.000 27.018 0.036 27.030 ;
    END
  END rw0_wd_in[24]
  PIN rw0_wd_in[25]
    DIRECTION INPUT ;
    USE SIGNAL ;
    SHAPE ABUTMENT ;
    PORT
      LAYER M2 ;
      RECT 0.000 27.402 0.036 27.414 ;
    END
  END rw0_wd_in[25]
  PIN rw0_wd_in[26]
    DIRECTION INPUT ;
    USE SIGNAL ;
    SHAPE ABUTMENT ;
    PORT
      LAYER M2 ;
      RECT 0.000 27.786 0.036 27.798 ;
    END
  END rw0_wd_in[26]
  PIN rw0_wd_in[27]
    DIRECTION INPUT ;
    USE SIGNAL ;
    SHAPE ABUTMENT ;
    PORT
      LAYER M2 ;
      RECT 0.000 28.170 0.036 28.182 ;
    END
  END rw0_wd_in[27]
  PIN rw0_wd_in[28]
    DIRECTION INPUT ;
    USE SIGNAL ;
    SHAPE ABUTMENT ;
    PORT
      LAYER M2 ;
      RECT 0.000 28.554 0.036 28.566 ;
    END
  END rw0_wd_in[28]
  PIN rw0_wd_in[29]
    DIRECTION INPUT ;
    USE SIGNAL ;
    SHAPE ABUTMENT ;
    PORT
      LAYER M2 ;
      RECT 0.000 28.938 0.036 28.950 ;
    END
  END rw0_wd_in[29]
  PIN rw0_wd_in[30]
    DIRECTION INPUT ;
    USE SIGNAL ;
    SHAPE ABUTMENT ;
    PORT
      LAYER M2 ;
      RECT 0.000 29.322 0.036 29.334 ;
    END
  END rw0_wd_in[30]
  PIN rw0_wd_in[31]
    DIRECTION INPUT ;
    USE SIGNAL ;
    SHAPE ABUTMENT ;
    PORT
      LAYER M2 ;
      RECT 0.000 29.706 0.036 29.718 ;
    END
  END rw0_wd_in[31]
  PIN rw0_wd_in[32]
    DIRECTION INPUT ;
    USE SIGNAL ;
    SHAPE ABUTMENT ;
    PORT
      LAYER M2 ;
      RECT 0.000 30.090 0.036 30.102 ;
    END
  END rw0_wd_in[32]
  PIN rw0_wd_in[33]
    DIRECTION INPUT ;
    USE SIGNAL ;
    SHAPE ABUTMENT ;
    PORT
      LAYER M2 ;
      RECT 0.000 30.474 0.036 30.486 ;
    END
  END rw0_wd_in[33]
  PIN rw0_wd_in[34]
    DIRECTION INPUT ;
    USE SIGNAL ;
    SHAPE ABUTMENT ;
    PORT
      LAYER M2 ;
      RECT 0.000 30.858 0.036 30.870 ;
    END
  END rw0_wd_in[34]
  PIN rw0_wd_in[35]
    DIRECTION INPUT ;
    USE SIGNAL ;
    SHAPE ABUTMENT ;
    PORT
      LAYER M2 ;
      RECT 0.000 31.242 0.036 31.254 ;
    END
  END rw0_wd_in[35]
  PIN rw0_wd_in[36]
    DIRECTION INPUT ;
    USE SIGNAL ;
    SHAPE ABUTMENT ;
    PORT
      LAYER M2 ;
      RECT 0.000 31.626 0.036 31.638 ;
    END
  END rw0_wd_in[36]
  PIN rw0_wd_in[37]
    DIRECTION INPUT ;
    USE SIGNAL ;
    SHAPE ABUTMENT ;
    PORT
      LAYER M2 ;
      RECT 0.000 32.010 0.036 32.022 ;
    END
  END rw0_wd_in[37]
  PIN rw0_wd_in[38]
    DIRECTION INPUT ;
    USE SIGNAL ;
    SHAPE ABUTMENT ;
    PORT
      LAYER M2 ;
      RECT 0.000 32.394 0.036 32.406 ;
    END
  END rw0_wd_in[38]
  PIN rw0_wd_in[39]
    DIRECTION INPUT ;
    USE SIGNAL ;
    SHAPE ABUTMENT ;
    PORT
      LAYER M2 ;
      RECT 0.000 32.778 0.036 32.790 ;
    END
  END rw0_wd_in[39]
  PIN rw0_wd_in[40]
    DIRECTION INPUT ;
    USE SIGNAL ;
    SHAPE ABUTMENT ;
    PORT
      LAYER M2 ;
      RECT 0.000 33.162 0.036 33.174 ;
    END
  END rw0_wd_in[40]
  PIN rw0_wd_in[41]
    DIRECTION INPUT ;
    USE SIGNAL ;
    SHAPE ABUTMENT ;
    PORT
      LAYER M2 ;
      RECT 0.000 33.546 0.036 33.558 ;
    END
  END rw0_wd_in[41]
  PIN rw0_wd_in[42]
    DIRECTION INPUT ;
    USE SIGNAL ;
    SHAPE ABUTMENT ;
    PORT
      LAYER M2 ;
      RECT 0.000 33.930 0.036 33.942 ;
    END
  END rw0_wd_in[42]
  PIN rw0_wd_in[43]
    DIRECTION INPUT ;
    USE SIGNAL ;
    SHAPE ABUTMENT ;
    PORT
      LAYER M2 ;
      RECT 0.000 34.314 0.036 34.326 ;
    END
  END rw0_wd_in[43]
  PIN rw0_wd_in[44]
    DIRECTION INPUT ;
    USE SIGNAL ;
    SHAPE ABUTMENT ;
    PORT
      LAYER M2 ;
      RECT 0.000 34.698 0.036 34.710 ;
    END
  END rw0_wd_in[44]
  PIN rw0_wd_in[45]
    DIRECTION INPUT ;
    USE SIGNAL ;
    SHAPE ABUTMENT ;
    PORT
      LAYER M2 ;
      RECT 0.000 35.082 0.036 35.094 ;
    END
  END rw0_wd_in[45]
  PIN rw0_wd_in[46]
    DIRECTION INPUT ;
    USE SIGNAL ;
    SHAPE ABUTMENT ;
    PORT
      LAYER M2 ;
      RECT 44.064 17.802 44.100 17.814 ;
    END
  END rw0_wd_in[46]
  PIN rw0_wd_in[47]
    DIRECTION INPUT ;
    USE SIGNAL ;
    SHAPE ABUTMENT ;
    PORT
      LAYER M2 ;
      RECT 44.064 18.186 44.100 18.198 ;
    END
  END rw0_wd_in[47]
  PIN rw0_wd_in[48]
    DIRECTION INPUT ;
    USE SIGNAL ;
    SHAPE ABUTMENT ;
    PORT
      LAYER M2 ;
      RECT 44.064 18.570 44.100 18.582 ;
    END
  END rw0_wd_in[48]
  PIN rw0_wd_in[49]
    DIRECTION INPUT ;
    USE SIGNAL ;
    SHAPE ABUTMENT ;
    PORT
      LAYER M2 ;
      RECT 44.064 18.954 44.100 18.966 ;
    END
  END rw0_wd_in[49]
  PIN rw0_wd_in[50]
    DIRECTION INPUT ;
    USE SIGNAL ;
    SHAPE ABUTMENT ;
    PORT
      LAYER M2 ;
      RECT 44.064 19.338 44.100 19.350 ;
    END
  END rw0_wd_in[50]
  PIN rw0_wd_in[51]
    DIRECTION INPUT ;
    USE SIGNAL ;
    SHAPE ABUTMENT ;
    PORT
      LAYER M2 ;
      RECT 44.064 19.722 44.100 19.734 ;
    END
  END rw0_wd_in[51]
  PIN rw0_wd_in[52]
    DIRECTION INPUT ;
    USE SIGNAL ;
    SHAPE ABUTMENT ;
    PORT
      LAYER M2 ;
      RECT 44.064 20.106 44.100 20.118 ;
    END
  END rw0_wd_in[52]
  PIN rw0_wd_in[53]
    DIRECTION INPUT ;
    USE SIGNAL ;
    SHAPE ABUTMENT ;
    PORT
      LAYER M2 ;
      RECT 44.064 20.490 44.100 20.502 ;
    END
  END rw0_wd_in[53]
  PIN rw0_wd_in[54]
    DIRECTION INPUT ;
    USE SIGNAL ;
    SHAPE ABUTMENT ;
    PORT
      LAYER M2 ;
      RECT 44.064 20.874 44.100 20.886 ;
    END
  END rw0_wd_in[54]
  PIN rw0_wd_in[55]
    DIRECTION INPUT ;
    USE SIGNAL ;
    SHAPE ABUTMENT ;
    PORT
      LAYER M2 ;
      RECT 44.064 21.258 44.100 21.270 ;
    END
  END rw0_wd_in[55]
  PIN rw0_wd_in[56]
    DIRECTION INPUT ;
    USE SIGNAL ;
    SHAPE ABUTMENT ;
    PORT
      LAYER M2 ;
      RECT 44.064 21.642 44.100 21.654 ;
    END
  END rw0_wd_in[56]
  PIN rw0_wd_in[57]
    DIRECTION INPUT ;
    USE SIGNAL ;
    SHAPE ABUTMENT ;
    PORT
      LAYER M2 ;
      RECT 44.064 22.026 44.100 22.038 ;
    END
  END rw0_wd_in[57]
  PIN rw0_wd_in[58]
    DIRECTION INPUT ;
    USE SIGNAL ;
    SHAPE ABUTMENT ;
    PORT
      LAYER M2 ;
      RECT 44.064 22.410 44.100 22.422 ;
    END
  END rw0_wd_in[58]
  PIN rw0_wd_in[59]
    DIRECTION INPUT ;
    USE SIGNAL ;
    SHAPE ABUTMENT ;
    PORT
      LAYER M2 ;
      RECT 44.064 22.794 44.100 22.806 ;
    END
  END rw0_wd_in[59]
  PIN rw0_wd_in[60]
    DIRECTION INPUT ;
    USE SIGNAL ;
    SHAPE ABUTMENT ;
    PORT
      LAYER M2 ;
      RECT 44.064 23.178 44.100 23.190 ;
    END
  END rw0_wd_in[60]
  PIN rw0_wd_in[61]
    DIRECTION INPUT ;
    USE SIGNAL ;
    SHAPE ABUTMENT ;
    PORT
      LAYER M2 ;
      RECT 44.064 23.562 44.100 23.574 ;
    END
  END rw0_wd_in[61]
  PIN rw0_wd_in[62]
    DIRECTION INPUT ;
    USE SIGNAL ;
    SHAPE ABUTMENT ;
    PORT
      LAYER M2 ;
      RECT 44.064 23.946 44.100 23.958 ;
    END
  END rw0_wd_in[62]
  PIN rw0_wd_in[63]
    DIRECTION INPUT ;
    USE SIGNAL ;
    SHAPE ABUTMENT ;
    PORT
      LAYER M2 ;
      RECT 44.064 24.330 44.100 24.342 ;
    END
  END rw0_wd_in[63]
  PIN rw0_wd_in[64]
    DIRECTION INPUT ;
    USE SIGNAL ;
    SHAPE ABUTMENT ;
    PORT
      LAYER M2 ;
      RECT 44.064 24.714 44.100 24.726 ;
    END
  END rw0_wd_in[64]
  PIN rw0_wd_in[65]
    DIRECTION INPUT ;
    USE SIGNAL ;
    SHAPE ABUTMENT ;
    PORT
      LAYER M2 ;
      RECT 44.064 25.098 44.100 25.110 ;
    END
  END rw0_wd_in[65]
  PIN rw0_wd_in[66]
    DIRECTION INPUT ;
    USE SIGNAL ;
    SHAPE ABUTMENT ;
    PORT
      LAYER M2 ;
      RECT 44.064 25.482 44.100 25.494 ;
    END
  END rw0_wd_in[66]
  PIN rw0_wd_in[67]
    DIRECTION INPUT ;
    USE SIGNAL ;
    SHAPE ABUTMENT ;
    PORT
      LAYER M2 ;
      RECT 44.064 25.866 44.100 25.878 ;
    END
  END rw0_wd_in[67]
  PIN rw0_wd_in[68]
    DIRECTION INPUT ;
    USE SIGNAL ;
    SHAPE ABUTMENT ;
    PORT
      LAYER M2 ;
      RECT 44.064 26.250 44.100 26.262 ;
    END
  END rw0_wd_in[68]
  PIN rw0_wd_in[69]
    DIRECTION INPUT ;
    USE SIGNAL ;
    SHAPE ABUTMENT ;
    PORT
      LAYER M2 ;
      RECT 44.064 26.634 44.100 26.646 ;
    END
  END rw0_wd_in[69]
  PIN rw0_wd_in[70]
    DIRECTION INPUT ;
    USE SIGNAL ;
    SHAPE ABUTMENT ;
    PORT
      LAYER M2 ;
      RECT 44.064 27.018 44.100 27.030 ;
    END
  END rw0_wd_in[70]
  PIN rw0_wd_in[71]
    DIRECTION INPUT ;
    USE SIGNAL ;
    SHAPE ABUTMENT ;
    PORT
      LAYER M2 ;
      RECT 44.064 27.402 44.100 27.414 ;
    END
  END rw0_wd_in[71]
  PIN rw0_wd_in[72]
    DIRECTION INPUT ;
    USE SIGNAL ;
    SHAPE ABUTMENT ;
    PORT
      LAYER M2 ;
      RECT 44.064 27.786 44.100 27.798 ;
    END
  END rw0_wd_in[72]
  PIN rw0_wd_in[73]
    DIRECTION INPUT ;
    USE SIGNAL ;
    SHAPE ABUTMENT ;
    PORT
      LAYER M2 ;
      RECT 44.064 28.170 44.100 28.182 ;
    END
  END rw0_wd_in[73]
  PIN rw0_wd_in[74]
    DIRECTION INPUT ;
    USE SIGNAL ;
    SHAPE ABUTMENT ;
    PORT
      LAYER M2 ;
      RECT 44.064 28.554 44.100 28.566 ;
    END
  END rw0_wd_in[74]
  PIN rw0_wd_in[75]
    DIRECTION INPUT ;
    USE SIGNAL ;
    SHAPE ABUTMENT ;
    PORT
      LAYER M2 ;
      RECT 44.064 28.938 44.100 28.950 ;
    END
  END rw0_wd_in[75]
  PIN rw0_wd_in[76]
    DIRECTION INPUT ;
    USE SIGNAL ;
    SHAPE ABUTMENT ;
    PORT
      LAYER M2 ;
      RECT 44.064 29.322 44.100 29.334 ;
    END
  END rw0_wd_in[76]
  PIN rw0_wd_in[77]
    DIRECTION INPUT ;
    USE SIGNAL ;
    SHAPE ABUTMENT ;
    PORT
      LAYER M2 ;
      RECT 44.064 29.706 44.100 29.718 ;
    END
  END rw0_wd_in[77]
  PIN rw0_wd_in[78]
    DIRECTION INPUT ;
    USE SIGNAL ;
    SHAPE ABUTMENT ;
    PORT
      LAYER M2 ;
      RECT 44.064 30.090 44.100 30.102 ;
    END
  END rw0_wd_in[78]
  PIN rw0_wd_in[79]
    DIRECTION INPUT ;
    USE SIGNAL ;
    SHAPE ABUTMENT ;
    PORT
      LAYER M2 ;
      RECT 44.064 30.474 44.100 30.486 ;
    END
  END rw0_wd_in[79]
  PIN rw0_wd_in[80]
    DIRECTION INPUT ;
    USE SIGNAL ;
    SHAPE ABUTMENT ;
    PORT
      LAYER M2 ;
      RECT 44.064 30.858 44.100 30.870 ;
    END
  END rw0_wd_in[80]
  PIN rw0_wd_in[81]
    DIRECTION INPUT ;
    USE SIGNAL ;
    SHAPE ABUTMENT ;
    PORT
      LAYER M2 ;
      RECT 44.064 31.242 44.100 31.254 ;
    END
  END rw0_wd_in[81]
  PIN rw0_wd_in[82]
    DIRECTION INPUT ;
    USE SIGNAL ;
    SHAPE ABUTMENT ;
    PORT
      LAYER M2 ;
      RECT 44.064 31.626 44.100 31.638 ;
    END
  END rw0_wd_in[82]
  PIN rw0_wd_in[83]
    DIRECTION INPUT ;
    USE SIGNAL ;
    SHAPE ABUTMENT ;
    PORT
      LAYER M2 ;
      RECT 44.064 32.010 44.100 32.022 ;
    END
  END rw0_wd_in[83]
  PIN rw0_wd_in[84]
    DIRECTION INPUT ;
    USE SIGNAL ;
    SHAPE ABUTMENT ;
    PORT
      LAYER M2 ;
      RECT 44.064 32.394 44.100 32.406 ;
    END
  END rw0_wd_in[84]
  PIN rw0_wd_in[85]
    DIRECTION INPUT ;
    USE SIGNAL ;
    SHAPE ABUTMENT ;
    PORT
      LAYER M2 ;
      RECT 44.064 32.778 44.100 32.790 ;
    END
  END rw0_wd_in[85]
  PIN rw0_wd_in[86]
    DIRECTION INPUT ;
    USE SIGNAL ;
    SHAPE ABUTMENT ;
    PORT
      LAYER M2 ;
      RECT 44.064 33.162 44.100 33.174 ;
    END
  END rw0_wd_in[86]
  PIN rw0_wd_in[87]
    DIRECTION INPUT ;
    USE SIGNAL ;
    SHAPE ABUTMENT ;
    PORT
      LAYER M2 ;
      RECT 44.064 33.546 44.100 33.558 ;
    END
  END rw0_wd_in[87]
  PIN rw0_wd_in[88]
    DIRECTION INPUT ;
    USE SIGNAL ;
    SHAPE ABUTMENT ;
    PORT
      LAYER M2 ;
      RECT 44.064 33.930 44.100 33.942 ;
    END
  END rw0_wd_in[88]
  PIN rw0_wd_in[89]
    DIRECTION INPUT ;
    USE SIGNAL ;
    SHAPE ABUTMENT ;
    PORT
      LAYER M2 ;
      RECT 44.064 34.314 44.100 34.326 ;
    END
  END rw0_wd_in[89]
  PIN rw0_wd_in[90]
    DIRECTION INPUT ;
    USE SIGNAL ;
    SHAPE ABUTMENT ;
    PORT
      LAYER M2 ;
      RECT 44.064 34.698 44.100 34.710 ;
    END
  END rw0_wd_in[90]
  PIN rw0_wd_in[91]
    DIRECTION INPUT ;
    USE SIGNAL ;
    SHAPE ABUTMENT ;
    PORT
      LAYER M2 ;
      RECT 44.064 35.082 44.100 35.094 ;
    END
  END rw0_wd_in[91]
  PIN rw0_wd_in[92]
    DIRECTION INPUT ;
    USE SIGNAL ;
    SHAPE ABUTMENT ;
    PORT
      LAYER M3 ;
      RECT 0.161 0.000 0.175 0.042 ;
    END
  END rw0_wd_in[92]
  PIN rw0_wd_in[93]
    DIRECTION INPUT ;
    USE SIGNAL ;
    SHAPE ABUTMENT ;
    PORT
      LAYER M3 ;
      RECT 0.385 0.000 0.399 0.042 ;
    END
  END rw0_wd_in[93]
  PIN rw0_wd_in[94]
    DIRECTION INPUT ;
    USE SIGNAL ;
    SHAPE ABUTMENT ;
    PORT
      LAYER M3 ;
      RECT 0.609 0.000 0.623 0.042 ;
    END
  END rw0_wd_in[94]
  PIN rw0_wd_in[95]
    DIRECTION INPUT ;
    USE SIGNAL ;
    SHAPE ABUTMENT ;
    PORT
      LAYER M3 ;
      RECT 0.833 0.000 0.847 0.042 ;
    END
  END rw0_wd_in[95]
  PIN rw0_wd_in[96]
    DIRECTION INPUT ;
    USE SIGNAL ;
    SHAPE ABUTMENT ;
    PORT
      LAYER M3 ;
      RECT 1.057 0.000 1.071 0.042 ;
    END
  END rw0_wd_in[96]
  PIN rw0_wd_in[97]
    DIRECTION INPUT ;
    USE SIGNAL ;
    SHAPE ABUTMENT ;
    PORT
      LAYER M3 ;
      RECT 1.281 0.000 1.295 0.042 ;
    END
  END rw0_wd_in[97]
  PIN rw0_wd_in[98]
    DIRECTION INPUT ;
    USE SIGNAL ;
    SHAPE ABUTMENT ;
    PORT
      LAYER M3 ;
      RECT 1.505 0.000 1.519 0.042 ;
    END
  END rw0_wd_in[98]
  PIN rw0_wd_in[99]
    DIRECTION INPUT ;
    USE SIGNAL ;
    SHAPE ABUTMENT ;
    PORT
      LAYER M3 ;
      RECT 1.729 0.000 1.743 0.042 ;
    END
  END rw0_wd_in[99]
  PIN rw0_wd_in[100]
    DIRECTION INPUT ;
    USE SIGNAL ;
    SHAPE ABUTMENT ;
    PORT
      LAYER M3 ;
      RECT 1.953 0.000 1.967 0.042 ;
    END
  END rw0_wd_in[100]
  PIN rw0_wd_in[101]
    DIRECTION INPUT ;
    USE SIGNAL ;
    SHAPE ABUTMENT ;
    PORT
      LAYER M3 ;
      RECT 2.177 0.000 2.191 0.042 ;
    END
  END rw0_wd_in[101]
  PIN rw0_wd_in[102]
    DIRECTION INPUT ;
    USE SIGNAL ;
    SHAPE ABUTMENT ;
    PORT
      LAYER M3 ;
      RECT 2.401 0.000 2.415 0.042 ;
    END
  END rw0_wd_in[102]
  PIN rw0_wd_in[103]
    DIRECTION INPUT ;
    USE SIGNAL ;
    SHAPE ABUTMENT ;
    PORT
      LAYER M3 ;
      RECT 2.625 0.000 2.639 0.042 ;
    END
  END rw0_wd_in[103]
  PIN rw0_wd_in[104]
    DIRECTION INPUT ;
    USE SIGNAL ;
    SHAPE ABUTMENT ;
    PORT
      LAYER M3 ;
      RECT 2.849 0.000 2.863 0.042 ;
    END
  END rw0_wd_in[104]
  PIN rw0_wd_in[105]
    DIRECTION INPUT ;
    USE SIGNAL ;
    SHAPE ABUTMENT ;
    PORT
      LAYER M3 ;
      RECT 3.073 0.000 3.087 0.042 ;
    END
  END rw0_wd_in[105]
  PIN rw0_wd_in[106]
    DIRECTION INPUT ;
    USE SIGNAL ;
    SHAPE ABUTMENT ;
    PORT
      LAYER M3 ;
      RECT 3.297 0.000 3.311 0.042 ;
    END
  END rw0_wd_in[106]
  PIN rw0_wd_in[107]
    DIRECTION INPUT ;
    USE SIGNAL ;
    SHAPE ABUTMENT ;
    PORT
      LAYER M3 ;
      RECT 3.521 0.000 3.535 0.042 ;
    END
  END rw0_wd_in[107]
  PIN rw0_wd_in[108]
    DIRECTION INPUT ;
    USE SIGNAL ;
    SHAPE ABUTMENT ;
    PORT
      LAYER M3 ;
      RECT 3.745 0.000 3.759 0.042 ;
    END
  END rw0_wd_in[108]
  PIN rw0_wd_in[109]
    DIRECTION INPUT ;
    USE SIGNAL ;
    SHAPE ABUTMENT ;
    PORT
      LAYER M3 ;
      RECT 3.969 0.000 3.983 0.042 ;
    END
  END rw0_wd_in[109]
  PIN rw0_wd_in[110]
    DIRECTION INPUT ;
    USE SIGNAL ;
    SHAPE ABUTMENT ;
    PORT
      LAYER M3 ;
      RECT 4.193 0.000 4.207 0.042 ;
    END
  END rw0_wd_in[110]
  PIN rw0_wd_in[111]
    DIRECTION INPUT ;
    USE SIGNAL ;
    SHAPE ABUTMENT ;
    PORT
      LAYER M3 ;
      RECT 4.417 0.000 4.431 0.042 ;
    END
  END rw0_wd_in[111]
  PIN rw0_wd_in[112]
    DIRECTION INPUT ;
    USE SIGNAL ;
    SHAPE ABUTMENT ;
    PORT
      LAYER M3 ;
      RECT 4.641 0.000 4.655 0.042 ;
    END
  END rw0_wd_in[112]
  PIN rw0_wd_in[113]
    DIRECTION INPUT ;
    USE SIGNAL ;
    SHAPE ABUTMENT ;
    PORT
      LAYER M3 ;
      RECT 4.865 0.000 4.879 0.042 ;
    END
  END rw0_wd_in[113]
  PIN rw0_wd_in[114]
    DIRECTION INPUT ;
    USE SIGNAL ;
    SHAPE ABUTMENT ;
    PORT
      LAYER M3 ;
      RECT 5.089 0.000 5.103 0.042 ;
    END
  END rw0_wd_in[114]
  PIN rw0_wd_in[115]
    DIRECTION INPUT ;
    USE SIGNAL ;
    SHAPE ABUTMENT ;
    PORT
      LAYER M3 ;
      RECT 5.313 0.000 5.327 0.042 ;
    END
  END rw0_wd_in[115]
  PIN rw0_wd_in[116]
    DIRECTION INPUT ;
    USE SIGNAL ;
    SHAPE ABUTMENT ;
    PORT
      LAYER M3 ;
      RECT 5.537 0.000 5.551 0.042 ;
    END
  END rw0_wd_in[116]
  PIN rw0_wd_in[117]
    DIRECTION INPUT ;
    USE SIGNAL ;
    SHAPE ABUTMENT ;
    PORT
      LAYER M3 ;
      RECT 5.761 0.000 5.775 0.042 ;
    END
  END rw0_wd_in[117]
  PIN rw0_wd_in[118]
    DIRECTION INPUT ;
    USE SIGNAL ;
    SHAPE ABUTMENT ;
    PORT
      LAYER M3 ;
      RECT 5.985 0.000 5.999 0.042 ;
    END
  END rw0_wd_in[118]
  PIN rw0_wd_in[119]
    DIRECTION INPUT ;
    USE SIGNAL ;
    SHAPE ABUTMENT ;
    PORT
      LAYER M3 ;
      RECT 6.209 0.000 6.223 0.042 ;
    END
  END rw0_wd_in[119]
  PIN rw0_wd_in[120]
    DIRECTION INPUT ;
    USE SIGNAL ;
    SHAPE ABUTMENT ;
    PORT
      LAYER M3 ;
      RECT 6.433 0.000 6.447 0.042 ;
    END
  END rw0_wd_in[120]
  PIN rw0_wd_in[121]
    DIRECTION INPUT ;
    USE SIGNAL ;
    SHAPE ABUTMENT ;
    PORT
      LAYER M3 ;
      RECT 6.657 0.000 6.671 0.042 ;
    END
  END rw0_wd_in[121]
  PIN rw0_wd_in[122]
    DIRECTION INPUT ;
    USE SIGNAL ;
    SHAPE ABUTMENT ;
    PORT
      LAYER M3 ;
      RECT 6.881 0.000 6.895 0.042 ;
    END
  END rw0_wd_in[122]
  PIN rw0_wd_in[123]
    DIRECTION INPUT ;
    USE SIGNAL ;
    SHAPE ABUTMENT ;
    PORT
      LAYER M3 ;
      RECT 7.105 0.000 7.119 0.042 ;
    END
  END rw0_wd_in[123]
  PIN rw0_wd_in[124]
    DIRECTION INPUT ;
    USE SIGNAL ;
    SHAPE ABUTMENT ;
    PORT
      LAYER M3 ;
      RECT 7.329 0.000 7.343 0.042 ;
    END
  END rw0_wd_in[124]
  PIN rw0_wd_in[125]
    DIRECTION INPUT ;
    USE SIGNAL ;
    SHAPE ABUTMENT ;
    PORT
      LAYER M3 ;
      RECT 7.553 0.000 7.567 0.042 ;
    END
  END rw0_wd_in[125]
  PIN rw0_wd_in[126]
    DIRECTION INPUT ;
    USE SIGNAL ;
    SHAPE ABUTMENT ;
    PORT
      LAYER M3 ;
      RECT 7.777 0.000 7.791 0.042 ;
    END
  END rw0_wd_in[126]
  PIN rw0_wd_in[127]
    DIRECTION INPUT ;
    USE SIGNAL ;
    SHAPE ABUTMENT ;
    PORT
      LAYER M3 ;
      RECT 8.001 0.000 8.015 0.042 ;
    END
  END rw0_wd_in[127]
  PIN rw0_wd_in[128]
    DIRECTION INPUT ;
    USE SIGNAL ;
    SHAPE ABUTMENT ;
    PORT
      LAYER M3 ;
      RECT 8.225 0.000 8.239 0.042 ;
    END
  END rw0_wd_in[128]
  PIN rw0_wd_in[129]
    DIRECTION INPUT ;
    USE SIGNAL ;
    SHAPE ABUTMENT ;
    PORT
      LAYER M3 ;
      RECT 8.449 0.000 8.463 0.042 ;
    END
  END rw0_wd_in[129]
  PIN rw0_wd_in[130]
    DIRECTION INPUT ;
    USE SIGNAL ;
    SHAPE ABUTMENT ;
    PORT
      LAYER M3 ;
      RECT 8.673 0.000 8.687 0.042 ;
    END
  END rw0_wd_in[130]
  PIN rw0_wd_in[131]
    DIRECTION INPUT ;
    USE SIGNAL ;
    SHAPE ABUTMENT ;
    PORT
      LAYER M3 ;
      RECT 8.897 0.000 8.911 0.042 ;
    END
  END rw0_wd_in[131]
  PIN rw0_wd_in[132]
    DIRECTION INPUT ;
    USE SIGNAL ;
    SHAPE ABUTMENT ;
    PORT
      LAYER M3 ;
      RECT 9.121 0.000 9.135 0.042 ;
    END
  END rw0_wd_in[132]
  PIN rw0_wd_in[133]
    DIRECTION INPUT ;
    USE SIGNAL ;
    SHAPE ABUTMENT ;
    PORT
      LAYER M3 ;
      RECT 9.345 0.000 9.359 0.042 ;
    END
  END rw0_wd_in[133]
  PIN rw0_wd_in[134]
    DIRECTION INPUT ;
    USE SIGNAL ;
    SHAPE ABUTMENT ;
    PORT
      LAYER M3 ;
      RECT 9.569 0.000 9.583 0.042 ;
    END
  END rw0_wd_in[134]
  PIN rw0_wd_in[135]
    DIRECTION INPUT ;
    USE SIGNAL ;
    SHAPE ABUTMENT ;
    PORT
      LAYER M3 ;
      RECT 9.793 0.000 9.807 0.042 ;
    END
  END rw0_wd_in[135]
  PIN rw0_wd_in[136]
    DIRECTION INPUT ;
    USE SIGNAL ;
    SHAPE ABUTMENT ;
    PORT
      LAYER M3 ;
      RECT 10.017 0.000 10.031 0.042 ;
    END
  END rw0_wd_in[136]
  PIN rw0_wd_in[137]
    DIRECTION INPUT ;
    USE SIGNAL ;
    SHAPE ABUTMENT ;
    PORT
      LAYER M3 ;
      RECT 10.241 0.000 10.255 0.042 ;
    END
  END rw0_wd_in[137]
  PIN rw0_wd_in[138]
    DIRECTION INPUT ;
    USE SIGNAL ;
    SHAPE ABUTMENT ;
    PORT
      LAYER M3 ;
      RECT 10.465 0.000 10.479 0.042 ;
    END
  END rw0_wd_in[138]
  PIN rw0_wd_in[139]
    DIRECTION INPUT ;
    USE SIGNAL ;
    SHAPE ABUTMENT ;
    PORT
      LAYER M3 ;
      RECT 10.689 0.000 10.703 0.042 ;
    END
  END rw0_wd_in[139]
  PIN rw0_wd_in[140]
    DIRECTION INPUT ;
    USE SIGNAL ;
    SHAPE ABUTMENT ;
    PORT
      LAYER M3 ;
      RECT 10.913 0.000 10.927 0.042 ;
    END
  END rw0_wd_in[140]
  PIN rw0_wd_in[141]
    DIRECTION INPUT ;
    USE SIGNAL ;
    SHAPE ABUTMENT ;
    PORT
      LAYER M3 ;
      RECT 11.137 0.000 11.151 0.042 ;
    END
  END rw0_wd_in[141]
  PIN rw0_wd_in[142]
    DIRECTION INPUT ;
    USE SIGNAL ;
    SHAPE ABUTMENT ;
    PORT
      LAYER M3 ;
      RECT 11.361 0.000 11.375 0.042 ;
    END
  END rw0_wd_in[142]
  PIN rw0_wd_in[143]
    DIRECTION INPUT ;
    USE SIGNAL ;
    SHAPE ABUTMENT ;
    PORT
      LAYER M3 ;
      RECT 11.585 0.000 11.599 0.042 ;
    END
  END rw0_wd_in[143]
  PIN rw0_wd_in[144]
    DIRECTION INPUT ;
    USE SIGNAL ;
    SHAPE ABUTMENT ;
    PORT
      LAYER M3 ;
      RECT 11.809 0.000 11.823 0.042 ;
    END
  END rw0_wd_in[144]
  PIN rw0_wd_in[145]
    DIRECTION INPUT ;
    USE SIGNAL ;
    SHAPE ABUTMENT ;
    PORT
      LAYER M3 ;
      RECT 12.033 0.000 12.047 0.042 ;
    END
  END rw0_wd_in[145]
  PIN rw0_wd_in[146]
    DIRECTION INPUT ;
    USE SIGNAL ;
    SHAPE ABUTMENT ;
    PORT
      LAYER M3 ;
      RECT 12.257 0.000 12.271 0.042 ;
    END
  END rw0_wd_in[146]
  PIN rw0_wd_in[147]
    DIRECTION INPUT ;
    USE SIGNAL ;
    SHAPE ABUTMENT ;
    PORT
      LAYER M3 ;
      RECT 12.481 0.000 12.495 0.042 ;
    END
  END rw0_wd_in[147]
  PIN rw0_wd_in[148]
    DIRECTION INPUT ;
    USE SIGNAL ;
    SHAPE ABUTMENT ;
    PORT
      LAYER M3 ;
      RECT 12.705 0.000 12.719 0.042 ;
    END
  END rw0_wd_in[148]
  PIN rw0_wd_in[149]
    DIRECTION INPUT ;
    USE SIGNAL ;
    SHAPE ABUTMENT ;
    PORT
      LAYER M3 ;
      RECT 12.929 0.000 12.943 0.042 ;
    END
  END rw0_wd_in[149]
  PIN rw0_wd_in[150]
    DIRECTION INPUT ;
    USE SIGNAL ;
    SHAPE ABUTMENT ;
    PORT
      LAYER M3 ;
      RECT 13.153 0.000 13.167 0.042 ;
    END
  END rw0_wd_in[150]
  PIN rw0_wd_in[151]
    DIRECTION INPUT ;
    USE SIGNAL ;
    SHAPE ABUTMENT ;
    PORT
      LAYER M3 ;
      RECT 13.377 0.000 13.391 0.042 ;
    END
  END rw0_wd_in[151]
  PIN rw0_wd_in[152]
    DIRECTION INPUT ;
    USE SIGNAL ;
    SHAPE ABUTMENT ;
    PORT
      LAYER M3 ;
      RECT 13.601 0.000 13.615 0.042 ;
    END
  END rw0_wd_in[152]
  PIN rw0_wd_in[153]
    DIRECTION INPUT ;
    USE SIGNAL ;
    SHAPE ABUTMENT ;
    PORT
      LAYER M3 ;
      RECT 13.825 0.000 13.839 0.042 ;
    END
  END rw0_wd_in[153]
  PIN rw0_wd_in[154]
    DIRECTION INPUT ;
    USE SIGNAL ;
    SHAPE ABUTMENT ;
    PORT
      LAYER M3 ;
      RECT 14.049 0.000 14.063 0.042 ;
    END
  END rw0_wd_in[154]
  PIN rw0_wd_in[155]
    DIRECTION INPUT ;
    USE SIGNAL ;
    SHAPE ABUTMENT ;
    PORT
      LAYER M3 ;
      RECT 14.273 0.000 14.287 0.042 ;
    END
  END rw0_wd_in[155]
  PIN rw0_wd_in[156]
    DIRECTION INPUT ;
    USE SIGNAL ;
    SHAPE ABUTMENT ;
    PORT
      LAYER M3 ;
      RECT 14.497 0.000 14.511 0.042 ;
    END
  END rw0_wd_in[156]
  PIN rw0_wd_in[157]
    DIRECTION INPUT ;
    USE SIGNAL ;
    SHAPE ABUTMENT ;
    PORT
      LAYER M3 ;
      RECT 14.721 0.000 14.735 0.042 ;
    END
  END rw0_wd_in[157]
  PIN rw0_wd_in[158]
    DIRECTION INPUT ;
    USE SIGNAL ;
    SHAPE ABUTMENT ;
    PORT
      LAYER M3 ;
      RECT 14.945 0.000 14.959 0.042 ;
    END
  END rw0_wd_in[158]
  PIN rw0_wd_in[159]
    DIRECTION INPUT ;
    USE SIGNAL ;
    SHAPE ABUTMENT ;
    PORT
      LAYER M3 ;
      RECT 15.169 0.000 15.183 0.042 ;
    END
  END rw0_wd_in[159]
  PIN rw0_wd_in[160]
    DIRECTION INPUT ;
    USE SIGNAL ;
    SHAPE ABUTMENT ;
    PORT
      LAYER M3 ;
      RECT 15.393 0.000 15.407 0.042 ;
    END
  END rw0_wd_in[160]
  PIN rw0_wd_in[161]
    DIRECTION INPUT ;
    USE SIGNAL ;
    SHAPE ABUTMENT ;
    PORT
      LAYER M3 ;
      RECT 15.617 0.000 15.631 0.042 ;
    END
  END rw0_wd_in[161]
  PIN rw0_wd_in[162]
    DIRECTION INPUT ;
    USE SIGNAL ;
    SHAPE ABUTMENT ;
    PORT
      LAYER M3 ;
      RECT 15.841 0.000 15.855 0.042 ;
    END
  END rw0_wd_in[162]
  PIN rw0_wd_in[163]
    DIRECTION INPUT ;
    USE SIGNAL ;
    SHAPE ABUTMENT ;
    PORT
      LAYER M3 ;
      RECT 16.065 0.000 16.079 0.042 ;
    END
  END rw0_wd_in[163]
  PIN rw0_wd_in[164]
    DIRECTION INPUT ;
    USE SIGNAL ;
    SHAPE ABUTMENT ;
    PORT
      LAYER M3 ;
      RECT 16.289 0.000 16.303 0.042 ;
    END
  END rw0_wd_in[164]
  PIN rw0_wd_in[165]
    DIRECTION INPUT ;
    USE SIGNAL ;
    SHAPE ABUTMENT ;
    PORT
      LAYER M3 ;
      RECT 16.513 0.000 16.527 0.042 ;
    END
  END rw0_wd_in[165]
  PIN rw0_wd_in[166]
    DIRECTION INPUT ;
    USE SIGNAL ;
    SHAPE ABUTMENT ;
    PORT
      LAYER M3 ;
      RECT 16.737 0.000 16.751 0.042 ;
    END
  END rw0_wd_in[166]
  PIN rw0_wd_in[167]
    DIRECTION INPUT ;
    USE SIGNAL ;
    SHAPE ABUTMENT ;
    PORT
      LAYER M3 ;
      RECT 16.961 0.000 16.975 0.042 ;
    END
  END rw0_wd_in[167]
  PIN rw0_wd_in[168]
    DIRECTION INPUT ;
    USE SIGNAL ;
    SHAPE ABUTMENT ;
    PORT
      LAYER M3 ;
      RECT 17.185 0.000 17.199 0.042 ;
    END
  END rw0_wd_in[168]
  PIN rw0_wd_in[169]
    DIRECTION INPUT ;
    USE SIGNAL ;
    SHAPE ABUTMENT ;
    PORT
      LAYER M3 ;
      RECT 17.409 0.000 17.423 0.042 ;
    END
  END rw0_wd_in[169]
  PIN rw0_wd_in[170]
    DIRECTION INPUT ;
    USE SIGNAL ;
    SHAPE ABUTMENT ;
    PORT
      LAYER M3 ;
      RECT 17.633 0.000 17.647 0.042 ;
    END
  END rw0_wd_in[170]
  PIN rw0_wd_in[171]
    DIRECTION INPUT ;
    USE SIGNAL ;
    SHAPE ABUTMENT ;
    PORT
      LAYER M3 ;
      RECT 17.857 0.000 17.871 0.042 ;
    END
  END rw0_wd_in[171]
  PIN rw0_wd_in[172]
    DIRECTION INPUT ;
    USE SIGNAL ;
    SHAPE ABUTMENT ;
    PORT
      LAYER M3 ;
      RECT 18.081 0.000 18.095 0.042 ;
    END
  END rw0_wd_in[172]
  PIN rw0_wd_in[173]
    DIRECTION INPUT ;
    USE SIGNAL ;
    SHAPE ABUTMENT ;
    PORT
      LAYER M3 ;
      RECT 18.305 0.000 18.319 0.042 ;
    END
  END rw0_wd_in[173]
  PIN rw0_wd_in[174]
    DIRECTION INPUT ;
    USE SIGNAL ;
    SHAPE ABUTMENT ;
    PORT
      LAYER M3 ;
      RECT 18.529 0.000 18.543 0.042 ;
    END
  END rw0_wd_in[174]
  PIN rw0_wd_in[175]
    DIRECTION INPUT ;
    USE SIGNAL ;
    SHAPE ABUTMENT ;
    PORT
      LAYER M3 ;
      RECT 18.753 0.000 18.767 0.042 ;
    END
  END rw0_wd_in[175]
  PIN rw0_wd_in[176]
    DIRECTION INPUT ;
    USE SIGNAL ;
    SHAPE ABUTMENT ;
    PORT
      LAYER M3 ;
      RECT 18.977 0.000 18.991 0.042 ;
    END
  END rw0_wd_in[176]
  PIN rw0_wd_in[177]
    DIRECTION INPUT ;
    USE SIGNAL ;
    SHAPE ABUTMENT ;
    PORT
      LAYER M3 ;
      RECT 19.201 0.000 19.215 0.042 ;
    END
  END rw0_wd_in[177]
  PIN rw0_wd_in[178]
    DIRECTION INPUT ;
    USE SIGNAL ;
    SHAPE ABUTMENT ;
    PORT
      LAYER M3 ;
      RECT 19.425 0.000 19.439 0.042 ;
    END
  END rw0_wd_in[178]
  PIN rw0_wd_in[179]
    DIRECTION INPUT ;
    USE SIGNAL ;
    SHAPE ABUTMENT ;
    PORT
      LAYER M3 ;
      RECT 19.649 0.000 19.663 0.042 ;
    END
  END rw0_wd_in[179]
  PIN rw0_wd_in[180]
    DIRECTION INPUT ;
    USE SIGNAL ;
    SHAPE ABUTMENT ;
    PORT
      LAYER M3 ;
      RECT 19.873 0.000 19.887 0.042 ;
    END
  END rw0_wd_in[180]
  PIN rw0_wd_in[181]
    DIRECTION INPUT ;
    USE SIGNAL ;
    SHAPE ABUTMENT ;
    PORT
      LAYER M3 ;
      RECT 20.097 0.000 20.111 0.042 ;
    END
  END rw0_wd_in[181]
  PIN rw0_wd_in[182]
    DIRECTION INPUT ;
    USE SIGNAL ;
    SHAPE ABUTMENT ;
    PORT
      LAYER M3 ;
      RECT 20.321 0.000 20.335 0.042 ;
    END
  END rw0_wd_in[182]
  PIN rw0_wd_in[183]
    DIRECTION INPUT ;
    USE SIGNAL ;
    SHAPE ABUTMENT ;
    PORT
      LAYER M3 ;
      RECT 20.545 0.000 20.559 0.042 ;
    END
  END rw0_wd_in[183]
  PIN rw0_rd_out[0]
    DIRECTION OUTPUT ;
    USE SIGNAL ;
    SHAPE ABUTMENT ;
    PORT
      LAYER M3 ;
      RECT 20.769 0.000 20.783 0.042 ;
    END
  END rw0_rd_out[0]
  PIN rw0_rd_out[1]
    DIRECTION OUTPUT ;
    USE SIGNAL ;
    SHAPE ABUTMENT ;
    PORT
      LAYER M3 ;
      RECT 20.993 0.000 21.007 0.042 ;
    END
  END rw0_rd_out[1]
  PIN rw0_rd_out[2]
    DIRECTION OUTPUT ;
    USE SIGNAL ;
    SHAPE ABUTMENT ;
    PORT
      LAYER M3 ;
      RECT 21.217 0.000 21.231 0.042 ;
    END
  END rw0_rd_out[2]
  PIN rw0_rd_out[3]
    DIRECTION OUTPUT ;
    USE SIGNAL ;
    SHAPE ABUTMENT ;
    PORT
      LAYER M3 ;
      RECT 21.441 0.000 21.455 0.042 ;
    END
  END rw0_rd_out[3]
  PIN rw0_rd_out[4]
    DIRECTION OUTPUT ;
    USE SIGNAL ;
    SHAPE ABUTMENT ;
    PORT
      LAYER M3 ;
      RECT 21.665 0.000 21.679 0.042 ;
    END
  END rw0_rd_out[4]
  PIN rw0_rd_out[5]
    DIRECTION OUTPUT ;
    USE SIGNAL ;
    SHAPE ABUTMENT ;
    PORT
      LAYER M3 ;
      RECT 21.889 0.000 21.903 0.042 ;
    END
  END rw0_rd_out[5]
  PIN rw0_rd_out[6]
    DIRECTION OUTPUT ;
    USE SIGNAL ;
    SHAPE ABUTMENT ;
    PORT
      LAYER M3 ;
      RECT 22.113 0.000 22.127 0.042 ;
    END
  END rw0_rd_out[6]
  PIN rw0_rd_out[7]
    DIRECTION OUTPUT ;
    USE SIGNAL ;
    SHAPE ABUTMENT ;
    PORT
      LAYER M3 ;
      RECT 22.337 0.000 22.351 0.042 ;
    END
  END rw0_rd_out[7]
  PIN rw0_rd_out[8]
    DIRECTION OUTPUT ;
    USE SIGNAL ;
    SHAPE ABUTMENT ;
    PORT
      LAYER M3 ;
      RECT 22.561 0.000 22.575 0.042 ;
    END
  END rw0_rd_out[8]
  PIN rw0_rd_out[9]
    DIRECTION OUTPUT ;
    USE SIGNAL ;
    SHAPE ABUTMENT ;
    PORT
      LAYER M3 ;
      RECT 22.785 0.000 22.799 0.042 ;
    END
  END rw0_rd_out[9]
  PIN rw0_rd_out[10]
    DIRECTION OUTPUT ;
    USE SIGNAL ;
    SHAPE ABUTMENT ;
    PORT
      LAYER M3 ;
      RECT 23.009 0.000 23.023 0.042 ;
    END
  END rw0_rd_out[10]
  PIN rw0_rd_out[11]
    DIRECTION OUTPUT ;
    USE SIGNAL ;
    SHAPE ABUTMENT ;
    PORT
      LAYER M3 ;
      RECT 23.233 0.000 23.247 0.042 ;
    END
  END rw0_rd_out[11]
  PIN rw0_rd_out[12]
    DIRECTION OUTPUT ;
    USE SIGNAL ;
    SHAPE ABUTMENT ;
    PORT
      LAYER M3 ;
      RECT 23.457 0.000 23.471 0.042 ;
    END
  END rw0_rd_out[12]
  PIN rw0_rd_out[13]
    DIRECTION OUTPUT ;
    USE SIGNAL ;
    SHAPE ABUTMENT ;
    PORT
      LAYER M3 ;
      RECT 23.681 0.000 23.695 0.042 ;
    END
  END rw0_rd_out[13]
  PIN rw0_rd_out[14]
    DIRECTION OUTPUT ;
    USE SIGNAL ;
    SHAPE ABUTMENT ;
    PORT
      LAYER M3 ;
      RECT 23.905 0.000 23.919 0.042 ;
    END
  END rw0_rd_out[14]
  PIN rw0_rd_out[15]
    DIRECTION OUTPUT ;
    USE SIGNAL ;
    SHAPE ABUTMENT ;
    PORT
      LAYER M3 ;
      RECT 24.129 0.000 24.143 0.042 ;
    END
  END rw0_rd_out[15]
  PIN rw0_rd_out[16]
    DIRECTION OUTPUT ;
    USE SIGNAL ;
    SHAPE ABUTMENT ;
    PORT
      LAYER M3 ;
      RECT 24.353 0.000 24.367 0.042 ;
    END
  END rw0_rd_out[16]
  PIN rw0_rd_out[17]
    DIRECTION OUTPUT ;
    USE SIGNAL ;
    SHAPE ABUTMENT ;
    PORT
      LAYER M3 ;
      RECT 24.577 0.000 24.591 0.042 ;
    END
  END rw0_rd_out[17]
  PIN rw0_rd_out[18]
    DIRECTION OUTPUT ;
    USE SIGNAL ;
    SHAPE ABUTMENT ;
    PORT
      LAYER M3 ;
      RECT 24.801 0.000 24.815 0.042 ;
    END
  END rw0_rd_out[18]
  PIN rw0_rd_out[19]
    DIRECTION OUTPUT ;
    USE SIGNAL ;
    SHAPE ABUTMENT ;
    PORT
      LAYER M3 ;
      RECT 25.025 0.000 25.039 0.042 ;
    END
  END rw0_rd_out[19]
  PIN rw0_rd_out[20]
    DIRECTION OUTPUT ;
    USE SIGNAL ;
    SHAPE ABUTMENT ;
    PORT
      LAYER M3 ;
      RECT 25.249 0.000 25.263 0.042 ;
    END
  END rw0_rd_out[20]
  PIN rw0_rd_out[21]
    DIRECTION OUTPUT ;
    USE SIGNAL ;
    SHAPE ABUTMENT ;
    PORT
      LAYER M3 ;
      RECT 25.473 0.000 25.487 0.042 ;
    END
  END rw0_rd_out[21]
  PIN rw0_rd_out[22]
    DIRECTION OUTPUT ;
    USE SIGNAL ;
    SHAPE ABUTMENT ;
    PORT
      LAYER M3 ;
      RECT 25.697 0.000 25.711 0.042 ;
    END
  END rw0_rd_out[22]
  PIN rw0_rd_out[23]
    DIRECTION OUTPUT ;
    USE SIGNAL ;
    SHAPE ABUTMENT ;
    PORT
      LAYER M3 ;
      RECT 25.921 0.000 25.935 0.042 ;
    END
  END rw0_rd_out[23]
  PIN rw0_rd_out[24]
    DIRECTION OUTPUT ;
    USE SIGNAL ;
    SHAPE ABUTMENT ;
    PORT
      LAYER M3 ;
      RECT 26.145 0.000 26.159 0.042 ;
    END
  END rw0_rd_out[24]
  PIN rw0_rd_out[25]
    DIRECTION OUTPUT ;
    USE SIGNAL ;
    SHAPE ABUTMENT ;
    PORT
      LAYER M3 ;
      RECT 26.369 0.000 26.383 0.042 ;
    END
  END rw0_rd_out[25]
  PIN rw0_rd_out[26]
    DIRECTION OUTPUT ;
    USE SIGNAL ;
    SHAPE ABUTMENT ;
    PORT
      LAYER M3 ;
      RECT 26.593 0.000 26.607 0.042 ;
    END
  END rw0_rd_out[26]
  PIN rw0_rd_out[27]
    DIRECTION OUTPUT ;
    USE SIGNAL ;
    SHAPE ABUTMENT ;
    PORT
      LAYER M3 ;
      RECT 26.817 0.000 26.831 0.042 ;
    END
  END rw0_rd_out[27]
  PIN rw0_rd_out[28]
    DIRECTION OUTPUT ;
    USE SIGNAL ;
    SHAPE ABUTMENT ;
    PORT
      LAYER M3 ;
      RECT 27.041 0.000 27.055 0.042 ;
    END
  END rw0_rd_out[28]
  PIN rw0_rd_out[29]
    DIRECTION OUTPUT ;
    USE SIGNAL ;
    SHAPE ABUTMENT ;
    PORT
      LAYER M3 ;
      RECT 27.265 0.000 27.279 0.042 ;
    END
  END rw0_rd_out[29]
  PIN rw0_rd_out[30]
    DIRECTION OUTPUT ;
    USE SIGNAL ;
    SHAPE ABUTMENT ;
    PORT
      LAYER M3 ;
      RECT 27.489 0.000 27.503 0.042 ;
    END
  END rw0_rd_out[30]
  PIN rw0_rd_out[31]
    DIRECTION OUTPUT ;
    USE SIGNAL ;
    SHAPE ABUTMENT ;
    PORT
      LAYER M3 ;
      RECT 27.713 0.000 27.727 0.042 ;
    END
  END rw0_rd_out[31]
  PIN rw0_rd_out[32]
    DIRECTION OUTPUT ;
    USE SIGNAL ;
    SHAPE ABUTMENT ;
    PORT
      LAYER M3 ;
      RECT 27.937 0.000 27.951 0.042 ;
    END
  END rw0_rd_out[32]
  PIN rw0_rd_out[33]
    DIRECTION OUTPUT ;
    USE SIGNAL ;
    SHAPE ABUTMENT ;
    PORT
      LAYER M3 ;
      RECT 28.161 0.000 28.175 0.042 ;
    END
  END rw0_rd_out[33]
  PIN rw0_rd_out[34]
    DIRECTION OUTPUT ;
    USE SIGNAL ;
    SHAPE ABUTMENT ;
    PORT
      LAYER M3 ;
      RECT 28.385 0.000 28.399 0.042 ;
    END
  END rw0_rd_out[34]
  PIN rw0_rd_out[35]
    DIRECTION OUTPUT ;
    USE SIGNAL ;
    SHAPE ABUTMENT ;
    PORT
      LAYER M3 ;
      RECT 28.609 0.000 28.623 0.042 ;
    END
  END rw0_rd_out[35]
  PIN rw0_rd_out[36]
    DIRECTION OUTPUT ;
    USE SIGNAL ;
    SHAPE ABUTMENT ;
    PORT
      LAYER M3 ;
      RECT 28.833 0.000 28.847 0.042 ;
    END
  END rw0_rd_out[36]
  PIN rw0_rd_out[37]
    DIRECTION OUTPUT ;
    USE SIGNAL ;
    SHAPE ABUTMENT ;
    PORT
      LAYER M3 ;
      RECT 29.057 0.000 29.071 0.042 ;
    END
  END rw0_rd_out[37]
  PIN rw0_rd_out[38]
    DIRECTION OUTPUT ;
    USE SIGNAL ;
    SHAPE ABUTMENT ;
    PORT
      LAYER M3 ;
      RECT 29.281 0.000 29.295 0.042 ;
    END
  END rw0_rd_out[38]
  PIN rw0_rd_out[39]
    DIRECTION OUTPUT ;
    USE SIGNAL ;
    SHAPE ABUTMENT ;
    PORT
      LAYER M3 ;
      RECT 29.505 0.000 29.519 0.042 ;
    END
  END rw0_rd_out[39]
  PIN rw0_rd_out[40]
    DIRECTION OUTPUT ;
    USE SIGNAL ;
    SHAPE ABUTMENT ;
    PORT
      LAYER M3 ;
      RECT 29.729 0.000 29.743 0.042 ;
    END
  END rw0_rd_out[40]
  PIN rw0_rd_out[41]
    DIRECTION OUTPUT ;
    USE SIGNAL ;
    SHAPE ABUTMENT ;
    PORT
      LAYER M3 ;
      RECT 29.953 0.000 29.967 0.042 ;
    END
  END rw0_rd_out[41]
  PIN rw0_rd_out[42]
    DIRECTION OUTPUT ;
    USE SIGNAL ;
    SHAPE ABUTMENT ;
    PORT
      LAYER M3 ;
      RECT 30.177 0.000 30.191 0.042 ;
    END
  END rw0_rd_out[42]
  PIN rw0_rd_out[43]
    DIRECTION OUTPUT ;
    USE SIGNAL ;
    SHAPE ABUTMENT ;
    PORT
      LAYER M3 ;
      RECT 30.401 0.000 30.415 0.042 ;
    END
  END rw0_rd_out[43]
  PIN rw0_rd_out[44]
    DIRECTION OUTPUT ;
    USE SIGNAL ;
    SHAPE ABUTMENT ;
    PORT
      LAYER M3 ;
      RECT 30.625 0.000 30.639 0.042 ;
    END
  END rw0_rd_out[44]
  PIN rw0_rd_out[45]
    DIRECTION OUTPUT ;
    USE SIGNAL ;
    SHAPE ABUTMENT ;
    PORT
      LAYER M3 ;
      RECT 30.849 0.000 30.863 0.042 ;
    END
  END rw0_rd_out[45]
  PIN rw0_rd_out[46]
    DIRECTION OUTPUT ;
    USE SIGNAL ;
    SHAPE ABUTMENT ;
    PORT
      LAYER M3 ;
      RECT 31.073 0.000 31.087 0.042 ;
    END
  END rw0_rd_out[46]
  PIN rw0_rd_out[47]
    DIRECTION OUTPUT ;
    USE SIGNAL ;
    SHAPE ABUTMENT ;
    PORT
      LAYER M3 ;
      RECT 31.297 0.000 31.311 0.042 ;
    END
  END rw0_rd_out[47]
  PIN rw0_rd_out[48]
    DIRECTION OUTPUT ;
    USE SIGNAL ;
    SHAPE ABUTMENT ;
    PORT
      LAYER M3 ;
      RECT 31.521 0.000 31.535 0.042 ;
    END
  END rw0_rd_out[48]
  PIN rw0_rd_out[49]
    DIRECTION OUTPUT ;
    USE SIGNAL ;
    SHAPE ABUTMENT ;
    PORT
      LAYER M3 ;
      RECT 31.745 0.000 31.759 0.042 ;
    END
  END rw0_rd_out[49]
  PIN rw0_rd_out[50]
    DIRECTION OUTPUT ;
    USE SIGNAL ;
    SHAPE ABUTMENT ;
    PORT
      LAYER M3 ;
      RECT 31.969 0.000 31.983 0.042 ;
    END
  END rw0_rd_out[50]
  PIN rw0_rd_out[51]
    DIRECTION OUTPUT ;
    USE SIGNAL ;
    SHAPE ABUTMENT ;
    PORT
      LAYER M3 ;
      RECT 32.193 0.000 32.207 0.042 ;
    END
  END rw0_rd_out[51]
  PIN rw0_rd_out[52]
    DIRECTION OUTPUT ;
    USE SIGNAL ;
    SHAPE ABUTMENT ;
    PORT
      LAYER M3 ;
      RECT 32.417 0.000 32.431 0.042 ;
    END
  END rw0_rd_out[52]
  PIN rw0_rd_out[53]
    DIRECTION OUTPUT ;
    USE SIGNAL ;
    SHAPE ABUTMENT ;
    PORT
      LAYER M3 ;
      RECT 32.641 0.000 32.655 0.042 ;
    END
  END rw0_rd_out[53]
  PIN rw0_rd_out[54]
    DIRECTION OUTPUT ;
    USE SIGNAL ;
    SHAPE ABUTMENT ;
    PORT
      LAYER M3 ;
      RECT 32.865 0.000 32.879 0.042 ;
    END
  END rw0_rd_out[54]
  PIN rw0_rd_out[55]
    DIRECTION OUTPUT ;
    USE SIGNAL ;
    SHAPE ABUTMENT ;
    PORT
      LAYER M3 ;
      RECT 33.089 0.000 33.103 0.042 ;
    END
  END rw0_rd_out[55]
  PIN rw0_rd_out[56]
    DIRECTION OUTPUT ;
    USE SIGNAL ;
    SHAPE ABUTMENT ;
    PORT
      LAYER M3 ;
      RECT 33.313 0.000 33.327 0.042 ;
    END
  END rw0_rd_out[56]
  PIN rw0_rd_out[57]
    DIRECTION OUTPUT ;
    USE SIGNAL ;
    SHAPE ABUTMENT ;
    PORT
      LAYER M3 ;
      RECT 33.537 0.000 33.551 0.042 ;
    END
  END rw0_rd_out[57]
  PIN rw0_rd_out[58]
    DIRECTION OUTPUT ;
    USE SIGNAL ;
    SHAPE ABUTMENT ;
    PORT
      LAYER M3 ;
      RECT 33.761 0.000 33.775 0.042 ;
    END
  END rw0_rd_out[58]
  PIN rw0_rd_out[59]
    DIRECTION OUTPUT ;
    USE SIGNAL ;
    SHAPE ABUTMENT ;
    PORT
      LAYER M3 ;
      RECT 33.985 0.000 33.999 0.042 ;
    END
  END rw0_rd_out[59]
  PIN rw0_rd_out[60]
    DIRECTION OUTPUT ;
    USE SIGNAL ;
    SHAPE ABUTMENT ;
    PORT
      LAYER M3 ;
      RECT 34.209 0.000 34.223 0.042 ;
    END
  END rw0_rd_out[60]
  PIN rw0_rd_out[61]
    DIRECTION OUTPUT ;
    USE SIGNAL ;
    SHAPE ABUTMENT ;
    PORT
      LAYER M3 ;
      RECT 34.433 0.000 34.447 0.042 ;
    END
  END rw0_rd_out[61]
  PIN rw0_rd_out[62]
    DIRECTION OUTPUT ;
    USE SIGNAL ;
    SHAPE ABUTMENT ;
    PORT
      LAYER M3 ;
      RECT 34.657 0.000 34.671 0.042 ;
    END
  END rw0_rd_out[62]
  PIN rw0_rd_out[63]
    DIRECTION OUTPUT ;
    USE SIGNAL ;
    SHAPE ABUTMENT ;
    PORT
      LAYER M3 ;
      RECT 34.881 0.000 34.895 0.042 ;
    END
  END rw0_rd_out[63]
  PIN rw0_rd_out[64]
    DIRECTION OUTPUT ;
    USE SIGNAL ;
    SHAPE ABUTMENT ;
    PORT
      LAYER M3 ;
      RECT 35.105 0.000 35.119 0.042 ;
    END
  END rw0_rd_out[64]
  PIN rw0_rd_out[65]
    DIRECTION OUTPUT ;
    USE SIGNAL ;
    SHAPE ABUTMENT ;
    PORT
      LAYER M3 ;
      RECT 35.329 0.000 35.343 0.042 ;
    END
  END rw0_rd_out[65]
  PIN rw0_rd_out[66]
    DIRECTION OUTPUT ;
    USE SIGNAL ;
    SHAPE ABUTMENT ;
    PORT
      LAYER M3 ;
      RECT 35.553 0.000 35.567 0.042 ;
    END
  END rw0_rd_out[66]
  PIN rw0_rd_out[67]
    DIRECTION OUTPUT ;
    USE SIGNAL ;
    SHAPE ABUTMENT ;
    PORT
      LAYER M3 ;
      RECT 35.777 0.000 35.791 0.042 ;
    END
  END rw0_rd_out[67]
  PIN rw0_rd_out[68]
    DIRECTION OUTPUT ;
    USE SIGNAL ;
    SHAPE ABUTMENT ;
    PORT
      LAYER M3 ;
      RECT 36.001 0.000 36.015 0.042 ;
    END
  END rw0_rd_out[68]
  PIN rw0_rd_out[69]
    DIRECTION OUTPUT ;
    USE SIGNAL ;
    SHAPE ABUTMENT ;
    PORT
      LAYER M3 ;
      RECT 36.225 0.000 36.239 0.042 ;
    END
  END rw0_rd_out[69]
  PIN rw0_rd_out[70]
    DIRECTION OUTPUT ;
    USE SIGNAL ;
    SHAPE ABUTMENT ;
    PORT
      LAYER M3 ;
      RECT 36.449 0.000 36.463 0.042 ;
    END
  END rw0_rd_out[70]
  PIN rw0_rd_out[71]
    DIRECTION OUTPUT ;
    USE SIGNAL ;
    SHAPE ABUTMENT ;
    PORT
      LAYER M3 ;
      RECT 36.673 0.000 36.687 0.042 ;
    END
  END rw0_rd_out[71]
  PIN rw0_rd_out[72]
    DIRECTION OUTPUT ;
    USE SIGNAL ;
    SHAPE ABUTMENT ;
    PORT
      LAYER M3 ;
      RECT 36.897 0.000 36.911 0.042 ;
    END
  END rw0_rd_out[72]
  PIN rw0_rd_out[73]
    DIRECTION OUTPUT ;
    USE SIGNAL ;
    SHAPE ABUTMENT ;
    PORT
      LAYER M3 ;
      RECT 37.121 0.000 37.135 0.042 ;
    END
  END rw0_rd_out[73]
  PIN rw0_rd_out[74]
    DIRECTION OUTPUT ;
    USE SIGNAL ;
    SHAPE ABUTMENT ;
    PORT
      LAYER M3 ;
      RECT 37.345 0.000 37.359 0.042 ;
    END
  END rw0_rd_out[74]
  PIN rw0_rd_out[75]
    DIRECTION OUTPUT ;
    USE SIGNAL ;
    SHAPE ABUTMENT ;
    PORT
      LAYER M3 ;
      RECT 37.569 0.000 37.583 0.042 ;
    END
  END rw0_rd_out[75]
  PIN rw0_rd_out[76]
    DIRECTION OUTPUT ;
    USE SIGNAL ;
    SHAPE ABUTMENT ;
    PORT
      LAYER M3 ;
      RECT 37.793 0.000 37.807 0.042 ;
    END
  END rw0_rd_out[76]
  PIN rw0_rd_out[77]
    DIRECTION OUTPUT ;
    USE SIGNAL ;
    SHAPE ABUTMENT ;
    PORT
      LAYER M3 ;
      RECT 38.017 0.000 38.031 0.042 ;
    END
  END rw0_rd_out[77]
  PIN rw0_rd_out[78]
    DIRECTION OUTPUT ;
    USE SIGNAL ;
    SHAPE ABUTMENT ;
    PORT
      LAYER M3 ;
      RECT 38.241 0.000 38.255 0.042 ;
    END
  END rw0_rd_out[78]
  PIN rw0_rd_out[79]
    DIRECTION OUTPUT ;
    USE SIGNAL ;
    SHAPE ABUTMENT ;
    PORT
      LAYER M3 ;
      RECT 38.465 0.000 38.479 0.042 ;
    END
  END rw0_rd_out[79]
  PIN rw0_rd_out[80]
    DIRECTION OUTPUT ;
    USE SIGNAL ;
    SHAPE ABUTMENT ;
    PORT
      LAYER M3 ;
      RECT 38.689 0.000 38.703 0.042 ;
    END
  END rw0_rd_out[80]
  PIN rw0_rd_out[81]
    DIRECTION OUTPUT ;
    USE SIGNAL ;
    SHAPE ABUTMENT ;
    PORT
      LAYER M3 ;
      RECT 38.913 0.000 38.927 0.042 ;
    END
  END rw0_rd_out[81]
  PIN rw0_rd_out[82]
    DIRECTION OUTPUT ;
    USE SIGNAL ;
    SHAPE ABUTMENT ;
    PORT
      LAYER M3 ;
      RECT 39.137 0.000 39.151 0.042 ;
    END
  END rw0_rd_out[82]
  PIN rw0_rd_out[83]
    DIRECTION OUTPUT ;
    USE SIGNAL ;
    SHAPE ABUTMENT ;
    PORT
      LAYER M3 ;
      RECT 39.361 0.000 39.375 0.042 ;
    END
  END rw0_rd_out[83]
  PIN rw0_rd_out[84]
    DIRECTION OUTPUT ;
    USE SIGNAL ;
    SHAPE ABUTMENT ;
    PORT
      LAYER M3 ;
      RECT 39.585 0.000 39.599 0.042 ;
    END
  END rw0_rd_out[84]
  PIN rw0_rd_out[85]
    DIRECTION OUTPUT ;
    USE SIGNAL ;
    SHAPE ABUTMENT ;
    PORT
      LAYER M3 ;
      RECT 39.809 0.000 39.823 0.042 ;
    END
  END rw0_rd_out[85]
  PIN rw0_rd_out[86]
    DIRECTION OUTPUT ;
    USE SIGNAL ;
    SHAPE ABUTMENT ;
    PORT
      LAYER M3 ;
      RECT 40.033 0.000 40.047 0.042 ;
    END
  END rw0_rd_out[86]
  PIN rw0_rd_out[87]
    DIRECTION OUTPUT ;
    USE SIGNAL ;
    SHAPE ABUTMENT ;
    PORT
      LAYER M3 ;
      RECT 40.257 0.000 40.271 0.042 ;
    END
  END rw0_rd_out[87]
  PIN rw0_rd_out[88]
    DIRECTION OUTPUT ;
    USE SIGNAL ;
    SHAPE ABUTMENT ;
    PORT
      LAYER M3 ;
      RECT 40.481 0.000 40.495 0.042 ;
    END
  END rw0_rd_out[88]
  PIN rw0_rd_out[89]
    DIRECTION OUTPUT ;
    USE SIGNAL ;
    SHAPE ABUTMENT ;
    PORT
      LAYER M3 ;
      RECT 40.705 0.000 40.719 0.042 ;
    END
  END rw0_rd_out[89]
  PIN rw0_rd_out[90]
    DIRECTION OUTPUT ;
    USE SIGNAL ;
    SHAPE ABUTMENT ;
    PORT
      LAYER M3 ;
      RECT 40.929 0.000 40.943 0.042 ;
    END
  END rw0_rd_out[90]
  PIN rw0_rd_out[91]
    DIRECTION OUTPUT ;
    USE SIGNAL ;
    SHAPE ABUTMENT ;
    PORT
      LAYER M3 ;
      RECT 41.153 0.000 41.167 0.042 ;
    END
  END rw0_rd_out[91]
  PIN rw0_rd_out[92]
    DIRECTION OUTPUT ;
    USE SIGNAL ;
    SHAPE ABUTMENT ;
    PORT
      LAYER M3 ;
      RECT 20.769 38.406 20.783 38.448 ;
    END
  END rw0_rd_out[92]
  PIN rw0_rd_out[93]
    DIRECTION OUTPUT ;
    USE SIGNAL ;
    SHAPE ABUTMENT ;
    PORT
      LAYER M3 ;
      RECT 20.993 38.406 21.007 38.448 ;
    END
  END rw0_rd_out[93]
  PIN rw0_rd_out[94]
    DIRECTION OUTPUT ;
    USE SIGNAL ;
    SHAPE ABUTMENT ;
    PORT
      LAYER M3 ;
      RECT 21.217 38.406 21.231 38.448 ;
    END
  END rw0_rd_out[94]
  PIN rw0_rd_out[95]
    DIRECTION OUTPUT ;
    USE SIGNAL ;
    SHAPE ABUTMENT ;
    PORT
      LAYER M3 ;
      RECT 21.441 38.406 21.455 38.448 ;
    END
  END rw0_rd_out[95]
  PIN rw0_rd_out[96]
    DIRECTION OUTPUT ;
    USE SIGNAL ;
    SHAPE ABUTMENT ;
    PORT
      LAYER M3 ;
      RECT 21.665 38.406 21.679 38.448 ;
    END
  END rw0_rd_out[96]
  PIN rw0_rd_out[97]
    DIRECTION OUTPUT ;
    USE SIGNAL ;
    SHAPE ABUTMENT ;
    PORT
      LAYER M3 ;
      RECT 21.889 38.406 21.903 38.448 ;
    END
  END rw0_rd_out[97]
  PIN rw0_rd_out[98]
    DIRECTION OUTPUT ;
    USE SIGNAL ;
    SHAPE ABUTMENT ;
    PORT
      LAYER M3 ;
      RECT 22.113 38.406 22.127 38.448 ;
    END
  END rw0_rd_out[98]
  PIN rw0_rd_out[99]
    DIRECTION OUTPUT ;
    USE SIGNAL ;
    SHAPE ABUTMENT ;
    PORT
      LAYER M3 ;
      RECT 22.337 38.406 22.351 38.448 ;
    END
  END rw0_rd_out[99]
  PIN rw0_rd_out[100]
    DIRECTION OUTPUT ;
    USE SIGNAL ;
    SHAPE ABUTMENT ;
    PORT
      LAYER M3 ;
      RECT 22.561 38.406 22.575 38.448 ;
    END
  END rw0_rd_out[100]
  PIN rw0_rd_out[101]
    DIRECTION OUTPUT ;
    USE SIGNAL ;
    SHAPE ABUTMENT ;
    PORT
      LAYER M3 ;
      RECT 22.785 38.406 22.799 38.448 ;
    END
  END rw0_rd_out[101]
  PIN rw0_rd_out[102]
    DIRECTION OUTPUT ;
    USE SIGNAL ;
    SHAPE ABUTMENT ;
    PORT
      LAYER M3 ;
      RECT 23.009 38.406 23.023 38.448 ;
    END
  END rw0_rd_out[102]
  PIN rw0_rd_out[103]
    DIRECTION OUTPUT ;
    USE SIGNAL ;
    SHAPE ABUTMENT ;
    PORT
      LAYER M3 ;
      RECT 23.233 38.406 23.247 38.448 ;
    END
  END rw0_rd_out[103]
  PIN rw0_rd_out[104]
    DIRECTION OUTPUT ;
    USE SIGNAL ;
    SHAPE ABUTMENT ;
    PORT
      LAYER M3 ;
      RECT 23.457 38.406 23.471 38.448 ;
    END
  END rw0_rd_out[104]
  PIN rw0_rd_out[105]
    DIRECTION OUTPUT ;
    USE SIGNAL ;
    SHAPE ABUTMENT ;
    PORT
      LAYER M3 ;
      RECT 23.681 38.406 23.695 38.448 ;
    END
  END rw0_rd_out[105]
  PIN rw0_rd_out[106]
    DIRECTION OUTPUT ;
    USE SIGNAL ;
    SHAPE ABUTMENT ;
    PORT
      LAYER M3 ;
      RECT 23.905 38.406 23.919 38.448 ;
    END
  END rw0_rd_out[106]
  PIN rw0_rd_out[107]
    DIRECTION OUTPUT ;
    USE SIGNAL ;
    SHAPE ABUTMENT ;
    PORT
      LAYER M3 ;
      RECT 24.129 38.406 24.143 38.448 ;
    END
  END rw0_rd_out[107]
  PIN rw0_rd_out[108]
    DIRECTION OUTPUT ;
    USE SIGNAL ;
    SHAPE ABUTMENT ;
    PORT
      LAYER M3 ;
      RECT 24.353 38.406 24.367 38.448 ;
    END
  END rw0_rd_out[108]
  PIN rw0_rd_out[109]
    DIRECTION OUTPUT ;
    USE SIGNAL ;
    SHAPE ABUTMENT ;
    PORT
      LAYER M3 ;
      RECT 24.577 38.406 24.591 38.448 ;
    END
  END rw0_rd_out[109]
  PIN rw0_rd_out[110]
    DIRECTION OUTPUT ;
    USE SIGNAL ;
    SHAPE ABUTMENT ;
    PORT
      LAYER M3 ;
      RECT 24.801 38.406 24.815 38.448 ;
    END
  END rw0_rd_out[110]
  PIN rw0_rd_out[111]
    DIRECTION OUTPUT ;
    USE SIGNAL ;
    SHAPE ABUTMENT ;
    PORT
      LAYER M3 ;
      RECT 25.025 38.406 25.039 38.448 ;
    END
  END rw0_rd_out[111]
  PIN rw0_rd_out[112]
    DIRECTION OUTPUT ;
    USE SIGNAL ;
    SHAPE ABUTMENT ;
    PORT
      LAYER M3 ;
      RECT 25.249 38.406 25.263 38.448 ;
    END
  END rw0_rd_out[112]
  PIN rw0_rd_out[113]
    DIRECTION OUTPUT ;
    USE SIGNAL ;
    SHAPE ABUTMENT ;
    PORT
      LAYER M3 ;
      RECT 25.473 38.406 25.487 38.448 ;
    END
  END rw0_rd_out[113]
  PIN rw0_rd_out[114]
    DIRECTION OUTPUT ;
    USE SIGNAL ;
    SHAPE ABUTMENT ;
    PORT
      LAYER M3 ;
      RECT 25.697 38.406 25.711 38.448 ;
    END
  END rw0_rd_out[114]
  PIN rw0_rd_out[115]
    DIRECTION OUTPUT ;
    USE SIGNAL ;
    SHAPE ABUTMENT ;
    PORT
      LAYER M3 ;
      RECT 25.921 38.406 25.935 38.448 ;
    END
  END rw0_rd_out[115]
  PIN rw0_rd_out[116]
    DIRECTION OUTPUT ;
    USE SIGNAL ;
    SHAPE ABUTMENT ;
    PORT
      LAYER M3 ;
      RECT 26.145 38.406 26.159 38.448 ;
    END
  END rw0_rd_out[116]
  PIN rw0_rd_out[117]
    DIRECTION OUTPUT ;
    USE SIGNAL ;
    SHAPE ABUTMENT ;
    PORT
      LAYER M3 ;
      RECT 26.369 38.406 26.383 38.448 ;
    END
  END rw0_rd_out[117]
  PIN rw0_rd_out[118]
    DIRECTION OUTPUT ;
    USE SIGNAL ;
    SHAPE ABUTMENT ;
    PORT
      LAYER M3 ;
      RECT 26.593 38.406 26.607 38.448 ;
    END
  END rw0_rd_out[118]
  PIN rw0_rd_out[119]
    DIRECTION OUTPUT ;
    USE SIGNAL ;
    SHAPE ABUTMENT ;
    PORT
      LAYER M3 ;
      RECT 26.817 38.406 26.831 38.448 ;
    END
  END rw0_rd_out[119]
  PIN rw0_rd_out[120]
    DIRECTION OUTPUT ;
    USE SIGNAL ;
    SHAPE ABUTMENT ;
    PORT
      LAYER M3 ;
      RECT 27.041 38.406 27.055 38.448 ;
    END
  END rw0_rd_out[120]
  PIN rw0_rd_out[121]
    DIRECTION OUTPUT ;
    USE SIGNAL ;
    SHAPE ABUTMENT ;
    PORT
      LAYER M3 ;
      RECT 27.265 38.406 27.279 38.448 ;
    END
  END rw0_rd_out[121]
  PIN rw0_rd_out[122]
    DIRECTION OUTPUT ;
    USE SIGNAL ;
    SHAPE ABUTMENT ;
    PORT
      LAYER M3 ;
      RECT 27.489 38.406 27.503 38.448 ;
    END
  END rw0_rd_out[122]
  PIN rw0_rd_out[123]
    DIRECTION OUTPUT ;
    USE SIGNAL ;
    SHAPE ABUTMENT ;
    PORT
      LAYER M3 ;
      RECT 27.713 38.406 27.727 38.448 ;
    END
  END rw0_rd_out[123]
  PIN rw0_rd_out[124]
    DIRECTION OUTPUT ;
    USE SIGNAL ;
    SHAPE ABUTMENT ;
    PORT
      LAYER M3 ;
      RECT 27.937 38.406 27.951 38.448 ;
    END
  END rw0_rd_out[124]
  PIN rw0_rd_out[125]
    DIRECTION OUTPUT ;
    USE SIGNAL ;
    SHAPE ABUTMENT ;
    PORT
      LAYER M3 ;
      RECT 28.161 38.406 28.175 38.448 ;
    END
  END rw0_rd_out[125]
  PIN rw0_rd_out[126]
    DIRECTION OUTPUT ;
    USE SIGNAL ;
    SHAPE ABUTMENT ;
    PORT
      LAYER M3 ;
      RECT 28.385 38.406 28.399 38.448 ;
    END
  END rw0_rd_out[126]
  PIN rw0_rd_out[127]
    DIRECTION OUTPUT ;
    USE SIGNAL ;
    SHAPE ABUTMENT ;
    PORT
      LAYER M3 ;
      RECT 28.609 38.406 28.623 38.448 ;
    END
  END rw0_rd_out[127]
  PIN rw0_rd_out[128]
    DIRECTION OUTPUT ;
    USE SIGNAL ;
    SHAPE ABUTMENT ;
    PORT
      LAYER M3 ;
      RECT 28.833 38.406 28.847 38.448 ;
    END
  END rw0_rd_out[128]
  PIN rw0_rd_out[129]
    DIRECTION OUTPUT ;
    USE SIGNAL ;
    SHAPE ABUTMENT ;
    PORT
      LAYER M3 ;
      RECT 29.057 38.406 29.071 38.448 ;
    END
  END rw0_rd_out[129]
  PIN rw0_rd_out[130]
    DIRECTION OUTPUT ;
    USE SIGNAL ;
    SHAPE ABUTMENT ;
    PORT
      LAYER M3 ;
      RECT 29.281 38.406 29.295 38.448 ;
    END
  END rw0_rd_out[130]
  PIN rw0_rd_out[131]
    DIRECTION OUTPUT ;
    USE SIGNAL ;
    SHAPE ABUTMENT ;
    PORT
      LAYER M3 ;
      RECT 29.505 38.406 29.519 38.448 ;
    END
  END rw0_rd_out[131]
  PIN rw0_rd_out[132]
    DIRECTION OUTPUT ;
    USE SIGNAL ;
    SHAPE ABUTMENT ;
    PORT
      LAYER M3 ;
      RECT 29.729 38.406 29.743 38.448 ;
    END
  END rw0_rd_out[132]
  PIN rw0_rd_out[133]
    DIRECTION OUTPUT ;
    USE SIGNAL ;
    SHAPE ABUTMENT ;
    PORT
      LAYER M3 ;
      RECT 29.953 38.406 29.967 38.448 ;
    END
  END rw0_rd_out[133]
  PIN rw0_rd_out[134]
    DIRECTION OUTPUT ;
    USE SIGNAL ;
    SHAPE ABUTMENT ;
    PORT
      LAYER M3 ;
      RECT 30.177 38.406 30.191 38.448 ;
    END
  END rw0_rd_out[134]
  PIN rw0_rd_out[135]
    DIRECTION OUTPUT ;
    USE SIGNAL ;
    SHAPE ABUTMENT ;
    PORT
      LAYER M3 ;
      RECT 30.401 38.406 30.415 38.448 ;
    END
  END rw0_rd_out[135]
  PIN rw0_rd_out[136]
    DIRECTION OUTPUT ;
    USE SIGNAL ;
    SHAPE ABUTMENT ;
    PORT
      LAYER M3 ;
      RECT 30.625 38.406 30.639 38.448 ;
    END
  END rw0_rd_out[136]
  PIN rw0_rd_out[137]
    DIRECTION OUTPUT ;
    USE SIGNAL ;
    SHAPE ABUTMENT ;
    PORT
      LAYER M3 ;
      RECT 30.849 38.406 30.863 38.448 ;
    END
  END rw0_rd_out[137]
  PIN rw0_rd_out[138]
    DIRECTION OUTPUT ;
    USE SIGNAL ;
    SHAPE ABUTMENT ;
    PORT
      LAYER M3 ;
      RECT 31.073 38.406 31.087 38.448 ;
    END
  END rw0_rd_out[138]
  PIN rw0_rd_out[139]
    DIRECTION OUTPUT ;
    USE SIGNAL ;
    SHAPE ABUTMENT ;
    PORT
      LAYER M3 ;
      RECT 31.297 38.406 31.311 38.448 ;
    END
  END rw0_rd_out[139]
  PIN rw0_rd_out[140]
    DIRECTION OUTPUT ;
    USE SIGNAL ;
    SHAPE ABUTMENT ;
    PORT
      LAYER M3 ;
      RECT 31.521 38.406 31.535 38.448 ;
    END
  END rw0_rd_out[140]
  PIN rw0_rd_out[141]
    DIRECTION OUTPUT ;
    USE SIGNAL ;
    SHAPE ABUTMENT ;
    PORT
      LAYER M3 ;
      RECT 31.745 38.406 31.759 38.448 ;
    END
  END rw0_rd_out[141]
  PIN rw0_rd_out[142]
    DIRECTION OUTPUT ;
    USE SIGNAL ;
    SHAPE ABUTMENT ;
    PORT
      LAYER M3 ;
      RECT 31.969 38.406 31.983 38.448 ;
    END
  END rw0_rd_out[142]
  PIN rw0_rd_out[143]
    DIRECTION OUTPUT ;
    USE SIGNAL ;
    SHAPE ABUTMENT ;
    PORT
      LAYER M3 ;
      RECT 32.193 38.406 32.207 38.448 ;
    END
  END rw0_rd_out[143]
  PIN rw0_rd_out[144]
    DIRECTION OUTPUT ;
    USE SIGNAL ;
    SHAPE ABUTMENT ;
    PORT
      LAYER M3 ;
      RECT 32.417 38.406 32.431 38.448 ;
    END
  END rw0_rd_out[144]
  PIN rw0_rd_out[145]
    DIRECTION OUTPUT ;
    USE SIGNAL ;
    SHAPE ABUTMENT ;
    PORT
      LAYER M3 ;
      RECT 32.641 38.406 32.655 38.448 ;
    END
  END rw0_rd_out[145]
  PIN rw0_rd_out[146]
    DIRECTION OUTPUT ;
    USE SIGNAL ;
    SHAPE ABUTMENT ;
    PORT
      LAYER M3 ;
      RECT 32.865 38.406 32.879 38.448 ;
    END
  END rw0_rd_out[146]
  PIN rw0_rd_out[147]
    DIRECTION OUTPUT ;
    USE SIGNAL ;
    SHAPE ABUTMENT ;
    PORT
      LAYER M3 ;
      RECT 33.089 38.406 33.103 38.448 ;
    END
  END rw0_rd_out[147]
  PIN rw0_rd_out[148]
    DIRECTION OUTPUT ;
    USE SIGNAL ;
    SHAPE ABUTMENT ;
    PORT
      LAYER M3 ;
      RECT 33.313 38.406 33.327 38.448 ;
    END
  END rw0_rd_out[148]
  PIN rw0_rd_out[149]
    DIRECTION OUTPUT ;
    USE SIGNAL ;
    SHAPE ABUTMENT ;
    PORT
      LAYER M3 ;
      RECT 33.537 38.406 33.551 38.448 ;
    END
  END rw0_rd_out[149]
  PIN rw0_rd_out[150]
    DIRECTION OUTPUT ;
    USE SIGNAL ;
    SHAPE ABUTMENT ;
    PORT
      LAYER M3 ;
      RECT 33.761 38.406 33.775 38.448 ;
    END
  END rw0_rd_out[150]
  PIN rw0_rd_out[151]
    DIRECTION OUTPUT ;
    USE SIGNAL ;
    SHAPE ABUTMENT ;
    PORT
      LAYER M3 ;
      RECT 33.985 38.406 33.999 38.448 ;
    END
  END rw0_rd_out[151]
  PIN rw0_rd_out[152]
    DIRECTION OUTPUT ;
    USE SIGNAL ;
    SHAPE ABUTMENT ;
    PORT
      LAYER M3 ;
      RECT 34.209 38.406 34.223 38.448 ;
    END
  END rw0_rd_out[152]
  PIN rw0_rd_out[153]
    DIRECTION OUTPUT ;
    USE SIGNAL ;
    SHAPE ABUTMENT ;
    PORT
      LAYER M3 ;
      RECT 34.433 38.406 34.447 38.448 ;
    END
  END rw0_rd_out[153]
  PIN rw0_rd_out[154]
    DIRECTION OUTPUT ;
    USE SIGNAL ;
    SHAPE ABUTMENT ;
    PORT
      LAYER M3 ;
      RECT 34.657 38.406 34.671 38.448 ;
    END
  END rw0_rd_out[154]
  PIN rw0_rd_out[155]
    DIRECTION OUTPUT ;
    USE SIGNAL ;
    SHAPE ABUTMENT ;
    PORT
      LAYER M3 ;
      RECT 34.881 38.406 34.895 38.448 ;
    END
  END rw0_rd_out[155]
  PIN rw0_rd_out[156]
    DIRECTION OUTPUT ;
    USE SIGNAL ;
    SHAPE ABUTMENT ;
    PORT
      LAYER M3 ;
      RECT 35.105 38.406 35.119 38.448 ;
    END
  END rw0_rd_out[156]
  PIN rw0_rd_out[157]
    DIRECTION OUTPUT ;
    USE SIGNAL ;
    SHAPE ABUTMENT ;
    PORT
      LAYER M3 ;
      RECT 35.329 38.406 35.343 38.448 ;
    END
  END rw0_rd_out[157]
  PIN rw0_rd_out[158]
    DIRECTION OUTPUT ;
    USE SIGNAL ;
    SHAPE ABUTMENT ;
    PORT
      LAYER M3 ;
      RECT 35.553 38.406 35.567 38.448 ;
    END
  END rw0_rd_out[158]
  PIN rw0_rd_out[159]
    DIRECTION OUTPUT ;
    USE SIGNAL ;
    SHAPE ABUTMENT ;
    PORT
      LAYER M3 ;
      RECT 35.777 38.406 35.791 38.448 ;
    END
  END rw0_rd_out[159]
  PIN rw0_rd_out[160]
    DIRECTION OUTPUT ;
    USE SIGNAL ;
    SHAPE ABUTMENT ;
    PORT
      LAYER M3 ;
      RECT 36.001 38.406 36.015 38.448 ;
    END
  END rw0_rd_out[160]
  PIN rw0_rd_out[161]
    DIRECTION OUTPUT ;
    USE SIGNAL ;
    SHAPE ABUTMENT ;
    PORT
      LAYER M3 ;
      RECT 36.225 38.406 36.239 38.448 ;
    END
  END rw0_rd_out[161]
  PIN rw0_rd_out[162]
    DIRECTION OUTPUT ;
    USE SIGNAL ;
    SHAPE ABUTMENT ;
    PORT
      LAYER M3 ;
      RECT 36.449 38.406 36.463 38.448 ;
    END
  END rw0_rd_out[162]
  PIN rw0_rd_out[163]
    DIRECTION OUTPUT ;
    USE SIGNAL ;
    SHAPE ABUTMENT ;
    PORT
      LAYER M3 ;
      RECT 36.673 38.406 36.687 38.448 ;
    END
  END rw0_rd_out[163]
  PIN rw0_rd_out[164]
    DIRECTION OUTPUT ;
    USE SIGNAL ;
    SHAPE ABUTMENT ;
    PORT
      LAYER M3 ;
      RECT 36.897 38.406 36.911 38.448 ;
    END
  END rw0_rd_out[164]
  PIN rw0_rd_out[165]
    DIRECTION OUTPUT ;
    USE SIGNAL ;
    SHAPE ABUTMENT ;
    PORT
      LAYER M3 ;
      RECT 37.121 38.406 37.135 38.448 ;
    END
  END rw0_rd_out[165]
  PIN rw0_rd_out[166]
    DIRECTION OUTPUT ;
    USE SIGNAL ;
    SHAPE ABUTMENT ;
    PORT
      LAYER M3 ;
      RECT 37.345 38.406 37.359 38.448 ;
    END
  END rw0_rd_out[166]
  PIN rw0_rd_out[167]
    DIRECTION OUTPUT ;
    USE SIGNAL ;
    SHAPE ABUTMENT ;
    PORT
      LAYER M3 ;
      RECT 37.569 38.406 37.583 38.448 ;
    END
  END rw0_rd_out[167]
  PIN rw0_rd_out[168]
    DIRECTION OUTPUT ;
    USE SIGNAL ;
    SHAPE ABUTMENT ;
    PORT
      LAYER M3 ;
      RECT 37.793 38.406 37.807 38.448 ;
    END
  END rw0_rd_out[168]
  PIN rw0_rd_out[169]
    DIRECTION OUTPUT ;
    USE SIGNAL ;
    SHAPE ABUTMENT ;
    PORT
      LAYER M3 ;
      RECT 38.017 38.406 38.031 38.448 ;
    END
  END rw0_rd_out[169]
  PIN rw0_rd_out[170]
    DIRECTION OUTPUT ;
    USE SIGNAL ;
    SHAPE ABUTMENT ;
    PORT
      LAYER M3 ;
      RECT 38.241 38.406 38.255 38.448 ;
    END
  END rw0_rd_out[170]
  PIN rw0_rd_out[171]
    DIRECTION OUTPUT ;
    USE SIGNAL ;
    SHAPE ABUTMENT ;
    PORT
      LAYER M3 ;
      RECT 38.465 38.406 38.479 38.448 ;
    END
  END rw0_rd_out[171]
  PIN rw0_rd_out[172]
    DIRECTION OUTPUT ;
    USE SIGNAL ;
    SHAPE ABUTMENT ;
    PORT
      LAYER M3 ;
      RECT 38.689 38.406 38.703 38.448 ;
    END
  END rw0_rd_out[172]
  PIN rw0_rd_out[173]
    DIRECTION OUTPUT ;
    USE SIGNAL ;
    SHAPE ABUTMENT ;
    PORT
      LAYER M3 ;
      RECT 38.913 38.406 38.927 38.448 ;
    END
  END rw0_rd_out[173]
  PIN rw0_rd_out[174]
    DIRECTION OUTPUT ;
    USE SIGNAL ;
    SHAPE ABUTMENT ;
    PORT
      LAYER M3 ;
      RECT 39.137 38.406 39.151 38.448 ;
    END
  END rw0_rd_out[174]
  PIN rw0_rd_out[175]
    DIRECTION OUTPUT ;
    USE SIGNAL ;
    SHAPE ABUTMENT ;
    PORT
      LAYER M3 ;
      RECT 39.361 38.406 39.375 38.448 ;
    END
  END rw0_rd_out[175]
  PIN rw0_rd_out[176]
    DIRECTION OUTPUT ;
    USE SIGNAL ;
    SHAPE ABUTMENT ;
    PORT
      LAYER M3 ;
      RECT 39.585 38.406 39.599 38.448 ;
    END
  END rw0_rd_out[176]
  PIN rw0_rd_out[177]
    DIRECTION OUTPUT ;
    USE SIGNAL ;
    SHAPE ABUTMENT ;
    PORT
      LAYER M3 ;
      RECT 39.809 38.406 39.823 38.448 ;
    END
  END rw0_rd_out[177]
  PIN rw0_rd_out[178]
    DIRECTION OUTPUT ;
    USE SIGNAL ;
    SHAPE ABUTMENT ;
    PORT
      LAYER M3 ;
      RECT 40.033 38.406 40.047 38.448 ;
    END
  END rw0_rd_out[178]
  PIN rw0_rd_out[179]
    DIRECTION OUTPUT ;
    USE SIGNAL ;
    SHAPE ABUTMENT ;
    PORT
      LAYER M3 ;
      RECT 40.257 38.406 40.271 38.448 ;
    END
  END rw0_rd_out[179]
  PIN rw0_rd_out[180]
    DIRECTION OUTPUT ;
    USE SIGNAL ;
    SHAPE ABUTMENT ;
    PORT
      LAYER M3 ;
      RECT 40.481 38.406 40.495 38.448 ;
    END
  END rw0_rd_out[180]
  PIN rw0_rd_out[181]
    DIRECTION OUTPUT ;
    USE SIGNAL ;
    SHAPE ABUTMENT ;
    PORT
      LAYER M3 ;
      RECT 40.705 38.406 40.719 38.448 ;
    END
  END rw0_rd_out[181]
  PIN rw0_rd_out[182]
    DIRECTION OUTPUT ;
    USE SIGNAL ;
    SHAPE ABUTMENT ;
    PORT
      LAYER M3 ;
      RECT 40.929 38.406 40.943 38.448 ;
    END
  END rw0_rd_out[182]
  PIN rw0_rd_out[183]
    DIRECTION OUTPUT ;
    USE SIGNAL ;
    SHAPE ABUTMENT ;
    PORT
      LAYER M3 ;
      RECT 41.153 38.406 41.167 38.448 ;
    END
  END rw0_rd_out[183]
  PIN rw0_addr_in[0]
    DIRECTION INPUT ;
    USE SIGNAL ;
    SHAPE ABUTMENT ;
    PORT
      LAYER M2 ;
      RECT 0.000 35.466 0.036 35.478 ;
    END
  END rw0_addr_in[0]
  PIN rw0_addr_in[1]
    DIRECTION INPUT ;
    USE SIGNAL ;
    SHAPE ABUTMENT ;
    PORT
      LAYER M2 ;
      RECT 0.000 35.850 0.036 35.862 ;
    END
  END rw0_addr_in[1]
  PIN rw0_addr_in[2]
    DIRECTION INPUT ;
    USE SIGNAL ;
    SHAPE ABUTMENT ;
    PORT
      LAYER M2 ;
      RECT 0.000 36.234 0.036 36.246 ;
    END
  END rw0_addr_in[2]
  PIN rw0_addr_in[3]
    DIRECTION INPUT ;
    USE SIGNAL ;
    SHAPE ABUTMENT ;
    PORT
      LAYER M2 ;
      RECT 44.064 35.466 44.100 35.478 ;
    END
  END rw0_addr_in[3]
  PIN rw0_addr_in[4]
    DIRECTION INPUT ;
    USE SIGNAL ;
    SHAPE ABUTMENT ;
    PORT
      LAYER M2 ;
      RECT 44.064 35.850 44.100 35.862 ;
    END
  END rw0_addr_in[4]
  PIN rw0_addr_in[5]
    DIRECTION INPUT ;
    USE SIGNAL ;
    SHAPE ABUTMENT ;
    PORT
      LAYER M2 ;
      RECT 44.064 36.234 44.100 36.246 ;
    END
  END rw0_addr_in[5]
  PIN rw0_we_in
    DIRECTION INPUT ;
    USE SIGNAL ;
    SHAPE ABUTMENT ;
    PORT
      LAYER M3 ;
      RECT 41.377 38.406 41.391 38.448 ;
    END
  END rw0_we_in
  PIN rw0_ce_in
    DIRECTION INPUT ;
    USE SIGNAL ;
    SHAPE ABUTMENT ;
    PORT
      LAYER M3 ;
      RECT 41.601 38.406 41.615 38.448 ;
    END
  END rw0_ce_in
  PIN rw0_clk
    DIRECTION INPUT ;
    USE SIGNAL ;
    SHAPE ABUTMENT ;
    PORT
      LAYER M3 ;
      RECT 41.825 38.406 41.839 38.448 ;
    END
  END rw0_clk
  PIN VSS
    DIRECTION INOUT ;
    USE GROUND ;
    PORT
      LAYER M4 ;
      RECT 0.168 0.120 43.932 0.168 ;
      RECT 0.168 0.504 43.932 0.552 ;
      RECT 0.168 0.888 43.932 0.936 ;
      RECT 0.168 1.272 43.932 1.320 ;
      RECT 0.168 1.656 43.932 1.704 ;
      RECT 0.168 2.040 43.932 2.088 ;
      RECT 0.168 2.424 43.932 2.472 ;
      RECT 0.168 2.808 43.932 2.856 ;
      RECT 0.168 3.192 43.932 3.240 ;
      RECT 0.168 3.576 43.932 3.624 ;
      RECT 0.168 3.960 43.932 4.008 ;
      RECT 0.168 4.344 43.932 4.392 ;
      RECT 0.168 4.728 43.932 4.776 ;
      RECT 0.168 5.112 43.932 5.160 ;
      RECT 0.168 5.496 43.932 5.544 ;
      RECT 0.168 5.880 43.932 5.928 ;
      RECT 0.168 6.264 43.932 6.312 ;
      RECT 0.168 6.648 43.932 6.696 ;
      RECT 0.168 7.032 43.932 7.080 ;
      RECT 0.168 7.416 43.932 7.464 ;
      RECT 0.168 7.800 43.932 7.848 ;
      RECT 0.168 8.184 43.932 8.232 ;
      RECT 0.168 8.568 43.932 8.616 ;
      RECT 0.168 8.952 43.932 9.000 ;
      RECT 0.168 9.336 43.932 9.384 ;
      RECT 0.168 9.720 43.932 9.768 ;
      RECT 0.168 10.104 43.932 10.152 ;
      RECT 0.168 10.488 43.932 10.536 ;
      RECT 0.168 10.872 43.932 10.920 ;
      RECT 0.168 11.256 43.932 11.304 ;
      RECT 0.168 11.640 43.932 11.688 ;
      RECT 0.168 12.024 43.932 12.072 ;
      RECT 0.168 12.408 43.932 12.456 ;
      RECT 0.168 12.792 43.932 12.840 ;
      RECT 0.168 13.176 43.932 13.224 ;
      RECT 0.168 13.560 43.932 13.608 ;
      RECT 0.168 13.944 43.932 13.992 ;
      RECT 0.168 14.328 43.932 14.376 ;
      RECT 0.168 14.712 43.932 14.760 ;
      RECT 0.168 15.096 43.932 15.144 ;
      RECT 0.168 15.480 43.932 15.528 ;
      RECT 0.168 15.864 43.932 15.912 ;
      RECT 0.168 16.248 43.932 16.296 ;
      RECT 0.168 16.632 43.932 16.680 ;
      RECT 0.168 17.016 43.932 17.064 ;
      RECT 0.168 17.400 43.932 17.448 ;
      RECT 0.168 17.784 43.932 17.832 ;
      RECT 0.168 18.168 43.932 18.216 ;
      RECT 0.168 18.552 43.932 18.600 ;
      RECT 0.168 18.936 43.932 18.984 ;
      RECT 0.168 19.320 43.932 19.368 ;
      RECT 0.168 19.704 43.932 19.752 ;
      RECT 0.168 20.088 43.932 20.136 ;
      RECT 0.168 20.472 43.932 20.520 ;
      RECT 0.168 20.856 43.932 20.904 ;
      RECT 0.168 21.240 43.932 21.288 ;
      RECT 0.168 21.624 43.932 21.672 ;
      RECT 0.168 22.008 43.932 22.056 ;
      RECT 0.168 22.392 43.932 22.440 ;
      RECT 0.168 22.776 43.932 22.824 ;
      RECT 0.168 23.160 43.932 23.208 ;
      RECT 0.168 23.544 43.932 23.592 ;
      RECT 0.168 23.928 43.932 23.976 ;
      RECT 0.168 24.312 43.932 24.360 ;
      RECT 0.168 24.696 43.932 24.744 ;
      RECT 0.168 25.080 43.932 25.128 ;
      RECT 0.168 25.464 43.932 25.512 ;
      RECT 0.168 25.848 43.932 25.896 ;
      RECT 0.168 26.232 43.932 26.280 ;
      RECT 0.168 26.616 43.932 26.664 ;
      RECT 0.168 27.000 43.932 27.048 ;
      RECT 0.168 27.384 43.932 27.432 ;
      RECT 0.168 27.768 43.932 27.816 ;
      RECT 0.168 28.152 43.932 28.200 ;
      RECT 0.168 28.536 43.932 28.584 ;
      RECT 0.168 28.920 43.932 28.968 ;
      RECT 0.168 29.304 43.932 29.352 ;
      RECT 0.168 29.688 43.932 29.736 ;
      RECT 0.168 30.072 43.932 30.120 ;
      RECT 0.168 30.456 43.932 30.504 ;
      RECT 0.168 30.840 43.932 30.888 ;
      RECT 0.168 31.224 43.932 31.272 ;
      RECT 0.168 31.608 43.932 31.656 ;
      RECT 0.168 31.992 43.932 32.040 ;
      RECT 0.168 32.376 43.932 32.424 ;
      RECT 0.168 32.760 43.932 32.808 ;
      RECT 0.168 33.144 43.932 33.192 ;
      RECT 0.168 33.528 43.932 33.576 ;
      RECT 0.168 33.912 43.932 33.960 ;
      RECT 0.168 34.296 43.932 34.344 ;
      RECT 0.168 34.680 43.932 34.728 ;
      RECT 0.168 35.064 43.932 35.112 ;
      RECT 0.168 35.448 43.932 35.496 ;
      RECT 0.168 35.832 43.932 35.880 ;
      RECT 0.168 36.216 43.932 36.264 ;
      RECT 0.168 36.600 43.932 36.648 ;
      RECT 0.168 36.984 43.932 37.032 ;
      RECT 0.168 37.368 43.932 37.416 ;
      RECT 0.168 37.752 43.932 37.800 ;
      RECT 0.168 38.136 43.932 38.184 ;
    END
  END VSS
  PIN VDD
    DIRECTION INOUT ;
    USE POWER ;
    PORT
      LAYER M4 ;
      RECT 0.168 0.312 43.932 0.360 ;
      RECT 0.168 0.696 43.932 0.744 ;
      RECT 0.168 1.080 43.932 1.128 ;
      RECT 0.168 1.464 43.932 1.512 ;
      RECT 0.168 1.848 43.932 1.896 ;
      RECT 0.168 2.232 43.932 2.280 ;
      RECT 0.168 2.616 43.932 2.664 ;
      RECT 0.168 3.000 43.932 3.048 ;
      RECT 0.168 3.384 43.932 3.432 ;
      RECT 0.168 3.768 43.932 3.816 ;
      RECT 0.168 4.152 43.932 4.200 ;
      RECT 0.168 4.536 43.932 4.584 ;
      RECT 0.168 4.920 43.932 4.968 ;
      RECT 0.168 5.304 43.932 5.352 ;
      RECT 0.168 5.688 43.932 5.736 ;
      RECT 0.168 6.072 43.932 6.120 ;
      RECT 0.168 6.456 43.932 6.504 ;
      RECT 0.168 6.840 43.932 6.888 ;
      RECT 0.168 7.224 43.932 7.272 ;
      RECT 0.168 7.608 43.932 7.656 ;
      RECT 0.168 7.992 43.932 8.040 ;
      RECT 0.168 8.376 43.932 8.424 ;
      RECT 0.168 8.760 43.932 8.808 ;
      RECT 0.168 9.144 43.932 9.192 ;
      RECT 0.168 9.528 43.932 9.576 ;
      RECT 0.168 9.912 43.932 9.960 ;
      RECT 0.168 10.296 43.932 10.344 ;
      RECT 0.168 10.680 43.932 10.728 ;
      RECT 0.168 11.064 43.932 11.112 ;
      RECT 0.168 11.448 43.932 11.496 ;
      RECT 0.168 11.832 43.932 11.880 ;
      RECT 0.168 12.216 43.932 12.264 ;
      RECT 0.168 12.600 43.932 12.648 ;
      RECT 0.168 12.984 43.932 13.032 ;
      RECT 0.168 13.368 43.932 13.416 ;
      RECT 0.168 13.752 43.932 13.800 ;
      RECT 0.168 14.136 43.932 14.184 ;
      RECT 0.168 14.520 43.932 14.568 ;
      RECT 0.168 14.904 43.932 14.952 ;
      RECT 0.168 15.288 43.932 15.336 ;
      RECT 0.168 15.672 43.932 15.720 ;
      RECT 0.168 16.056 43.932 16.104 ;
      RECT 0.168 16.440 43.932 16.488 ;
      RECT 0.168 16.824 43.932 16.872 ;
      RECT 0.168 17.208 43.932 17.256 ;
      RECT 0.168 17.592 43.932 17.640 ;
      RECT 0.168 17.976 43.932 18.024 ;
      RECT 0.168 18.360 43.932 18.408 ;
      RECT 0.168 18.744 43.932 18.792 ;
      RECT 0.168 19.128 43.932 19.176 ;
      RECT 0.168 19.512 43.932 19.560 ;
      RECT 0.168 19.896 43.932 19.944 ;
      RECT 0.168 20.280 43.932 20.328 ;
      RECT 0.168 20.664 43.932 20.712 ;
      RECT 0.168 21.048 43.932 21.096 ;
      RECT 0.168 21.432 43.932 21.480 ;
      RECT 0.168 21.816 43.932 21.864 ;
      RECT 0.168 22.200 43.932 22.248 ;
      RECT 0.168 22.584 43.932 22.632 ;
      RECT 0.168 22.968 43.932 23.016 ;
      RECT 0.168 23.352 43.932 23.400 ;
      RECT 0.168 23.736 43.932 23.784 ;
      RECT 0.168 24.120 43.932 24.168 ;
      RECT 0.168 24.504 43.932 24.552 ;
      RECT 0.168 24.888 43.932 24.936 ;
      RECT 0.168 25.272 43.932 25.320 ;
      RECT 0.168 25.656 43.932 25.704 ;
      RECT 0.168 26.040 43.932 26.088 ;
      RECT 0.168 26.424 43.932 26.472 ;
      RECT 0.168 26.808 43.932 26.856 ;
      RECT 0.168 27.192 43.932 27.240 ;
      RECT 0.168 27.576 43.932 27.624 ;
      RECT 0.168 27.960 43.932 28.008 ;
      RECT 0.168 28.344 43.932 28.392 ;
      RECT 0.168 28.728 43.932 28.776 ;
      RECT 0.168 29.112 43.932 29.160 ;
      RECT 0.168 29.496 43.932 29.544 ;
      RECT 0.168 29.880 43.932 29.928 ;
      RECT 0.168 30.264 43.932 30.312 ;
      RECT 0.168 30.648 43.932 30.696 ;
      RECT 0.168 31.032 43.932 31.080 ;
      RECT 0.168 31.416 43.932 31.464 ;
      RECT 0.168 31.800 43.932 31.848 ;
      RECT 0.168 32.184 43.932 32.232 ;
      RECT 0.168 32.568 43.932 32.616 ;
      RECT 0.168 32.952 43.932 33.000 ;
      RECT 0.168 33.336 43.932 33.384 ;
      RECT 0.168 33.720 43.932 33.768 ;
      RECT 0.168 34.104 43.932 34.152 ;
      RECT 0.168 34.488 43.932 34.536 ;
      RECT 0.168 34.872 43.932 34.920 ;
      RECT 0.168 35.256 43.932 35.304 ;
      RECT 0.168 35.640 43.932 35.688 ;
      RECT 0.168 36.024 43.932 36.072 ;
      RECT 0.168 36.408 43.932 36.456 ;
      RECT 0.168 36.792 43.932 36.840 ;
      RECT 0.168 37.176 43.932 37.224 ;
      RECT 0.168 37.560 43.932 37.608 ;
      RECT 0.168 37.944 43.932 37.992 ;
      RECT 0.168 38.328 43.932 38.376 ;
    END
  END VDD
  OBS
    LAYER M1 ;
    RECT 0 0 44.100 38.448 ;
    LAYER M2 ;
    RECT 0 0 44.100 38.448 ;
    LAYER M3 ;
    RECT 0 0 44.100 38.448 ;
    LAYER M4 ;
    RECT 0 0 44.100 38.448 ;
  END
END fakeram_64x184_1rw

END LIBRARY
